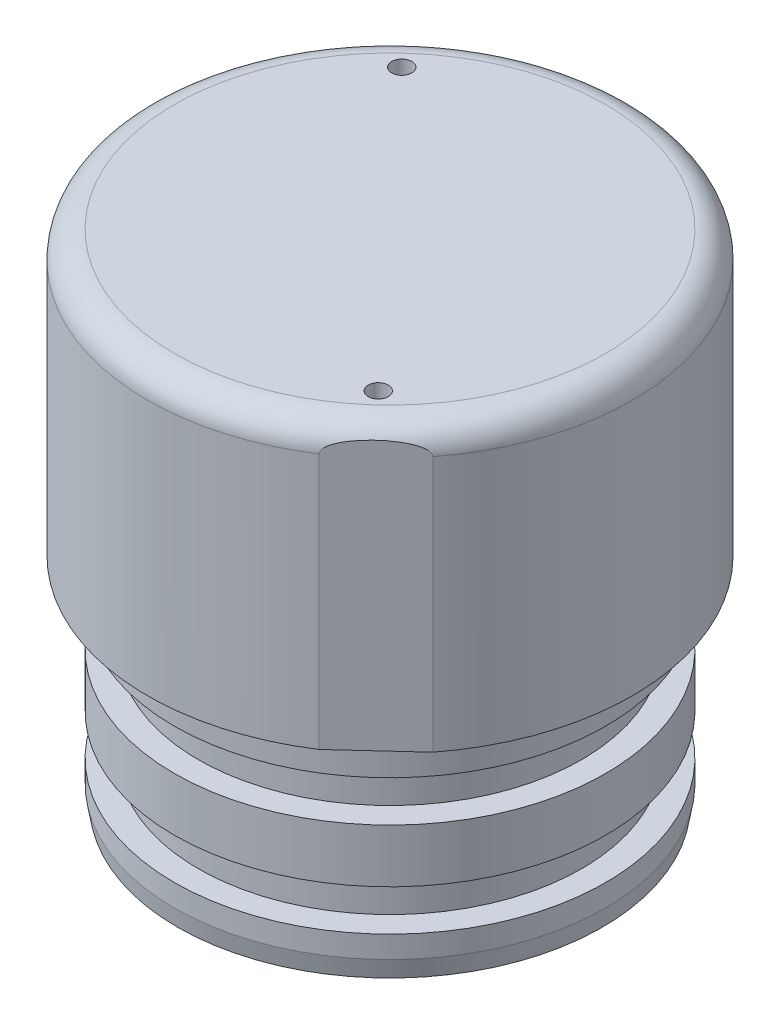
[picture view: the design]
ISO-10303-21;
HEADER;
FILE_DESCRIPTION(('STEP AP214'),'2;1');
FILE_NAME('part.step','',(''),(''),'','','');
FILE_SCHEMA(('AUTOMOTIVE_DESIGN { 1 0 10303 214 1 1 1 1 }'));
ENDSEC;
DATA;
#1=APPLICATION_CONTEXT('core data for automotive mechanical design processes');
#2=APPLICATION_PROTOCOL_DEFINITION('international standard','automotive_design',2000,#1);
#3=PRODUCT_CONTEXT('',#1,'mechanical');
#4=PRODUCT('Part','Part','',(#3));
#5=PRODUCT_RELATED_PRODUCT_CATEGORY('part','',(#4));
#6=PRODUCT_DEFINITION_FORMATION('','',#4);
#7=PRODUCT_DEFINITION_CONTEXT('part definition',#1,'design');
#8=PRODUCT_DEFINITION('design','',#6,#7);
#9=PRODUCT_DEFINITION_SHAPE('','',#8);
#10=(LENGTH_UNIT() NAMED_UNIT(*) SI_UNIT(.MILLI.,.METRE.));
#11=(NAMED_UNIT(*) PLANE_ANGLE_UNIT() SI_UNIT($,.RADIAN.));
#12=(NAMED_UNIT(*) SI_UNIT($,.STERADIAN.) SOLID_ANGLE_UNIT());
#13=UNCERTAINTY_MEASURE_WITH_UNIT(LENGTH_MEASURE(1.E-05),#10,'distance_accuracy_value','');
#14=(GEOMETRIC_REPRESENTATION_CONTEXT(3) GLOBAL_UNCERTAINTY_ASSIGNED_CONTEXT((#13)) GLOBAL_UNIT_ASSIGNED_CONTEXT((#10,
#11,#12)) REPRESENTATION_CONTEXT('',''));
#15=CARTESIAN_POINT('',(0.,0.,0.));
#16=DIRECTION('',(0.,0.,1.));
#17=DIRECTION('',(1.,0.,0.));
#18=AXIS2_PLACEMENT_3D('',#15,#16,#17);
#19=CARTESIAN_POINT('',(0.,0.,0.));
#20=DIRECTION('',(0.,1.,0.));
#21=DIRECTION('',(0.,0.,1.));
#22=AXIS2_PLACEMENT_3D('',#19,#20,#21);
#23=PLANE('',#22);
#24=CARTESIAN_POINT('',(0.,0.,0.));
#25=DIRECTION('',(0.,1.,0.));
#26=DIRECTION('',(0.,0.,1.));
#27=AXIS2_PLACEMENT_3D('',#24,#25,#26);
#28=CIRCLE('',#27,25.4);
#29=CARTESIAN_POINT('',(0.,0.,25.4));
#30=VERTEX_POINT('',#29);
#31=EDGE_CURVE('E132',#30,#30,#28,.T.);
#32=ORIENTED_EDGE('',*,*,#31,.T.);
#33=EDGE_LOOP('',(#32));
#34=FACE_BOUND('',#33,.T.);
#35=DIRECTION('',(-0.736097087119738,0.,0.676875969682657));
#36=VECTOR('',#35,1.);
#37=CARTESIAN_POINT('',(-19.0730956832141,0.,-20.7418357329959));
#38=LINE('',#37,#36);
#39=CARTESIAN_POINT('',(-15.5796269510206,0.,-23.9542449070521));
#40=VERTEX_POINT('',#39);
#41=CARTESIAN_POINT('',(-22.5665644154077,0.,-17.5294265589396));
#42=VERTEX_POINT('',#41);
#43=EDGE_CURVE('E106',#40,#42,#38,.T.);
#44=ORIENTED_EDGE('',*,*,#43,.F.);
#45=CARTESIAN_POINT('',(0.,0.,0.));
#46=DIRECTION('',(0.,1.,0.));
#47=DIRECTION('',(0.,0.,1.));
#48=AXIS2_PLACEMENT_3D('',#45,#46,#47);
#49=CIRCLE('',#48,28.575);
#50=CARTESIAN_POINT('',(22.5665644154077,0.,17.5294265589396));
#51=VERTEX_POINT('',#50);
#52=EDGE_CURVE('E127',#51,#40,#49,.T.);
#53=ORIENTED_EDGE('',*,*,#52,.F.);
#54=DIRECTION('',(0.736097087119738,0.,-0.676875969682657));
#55=VECTOR('',#54,1.);
#56=CARTESIAN_POINT('',(19.0730956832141,0.,20.7418357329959));
#57=LINE('',#56,#55);
#58=CARTESIAN_POINT('',(15.5796269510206,0.,23.9542449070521));
#59=VERTEX_POINT('',#58);
#60=EDGE_CURVE('E125',#59,#51,#57,.T.);
#61=ORIENTED_EDGE('',*,*,#60,.F.);
#62=EDGE_CURVE('E120',#42,#59,#49,.T.);
#63=ORIENTED_EDGE('',*,*,#62,.F.);
#64=EDGE_LOOP('',(#44,#53,#61,#63));
#65=FACE_BOUND('',#64,.T.);
#66=ADVANCED_FACE('F42',(#34,#65),#23,.F.);
#67=CARTESIAN_POINT('',(0.,30.1498,0.));
#68=DIRECTION('',(0.,1.,0.));
#69=DIRECTION('',(0.,0.,1.));
#70=AXIS2_PLACEMENT_3D('',#67,#68,#69);
#71=TOROIDAL_SURFACE('',#70,25.4,3.175);
#72=CARTESIAN_POINT('',(0.,33.3248,0.));
#73=DIRECTION('',(0.,1.,0.));
#74=DIRECTION('',(0.,0.,1.));
#75=AXIS2_PLACEMENT_3D('',#72,#73,#74);
#76=CIRCLE('',#75,25.4);
#77=CARTESIAN_POINT('',(0.,33.3248,25.4));
#78=VERTEX_POINT('',#77);
#79=EDGE_CURVE('E425',#78,#78,#76,.T.);
#80=ORIENTED_EDGE('',*,*,#79,.F.);
#81=EDGE_LOOP('',(#80));
#82=FACE_BOUND('',#81,.T.);
#83=CARTESIAN_POINT('',(0.,30.1498,0.));
#84=DIRECTION('',(0.,1.,0.));
#85=DIRECTION('',(0.,0.,1.));
#86=AXIS2_PLACEMENT_3D('',#83,#84,#85);
#87=CIRCLE('',#86,28.575);
#88=CARTESIAN_POINT('',(-15.5796269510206,30.1498000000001,-23.9542449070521));
#89=VERTEX_POINT('',#88);
#90=CARTESIAN_POINT('',(-0.531127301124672,30.1498,-28.5700635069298));
#91=VERTEX_POINT('',#90);
#92=EDGE_CURVE('E428',#89,#91,#87,.F.);
#93=ORIENTED_EDGE('',*,*,#92,.F.);
#94=CARTESIAN_POINT('',(-15.5817128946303,30.0951413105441,-23.952326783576));
#95=CARTESIAN_POINT('',(-15.5792110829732,30.1268458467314,-23.9546273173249));
#96=CARTESIAN_POINT('',(-15.5789577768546,30.1588034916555,-23.9548602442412));
#97=CARTESIAN_POINT('',(-15.5825959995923,30.2219737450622,-23.9515147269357));
#98=CARTESIAN_POINT('',(-15.5864466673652,30.2531905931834,-23.9479738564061));
#99=CARTESIAN_POINT('',(-15.5978925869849,30.3142250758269,-23.9374487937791));
#100=CARTESIAN_POINT('',(-15.6054798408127,30.3440455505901,-23.9304719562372));
#101=CARTESIAN_POINT('',(-15.62373561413,30.4019326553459,-23.913684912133));
#102=CARTESIAN_POINT('',(-15.634411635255,30.4299948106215,-23.9038678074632));
#103=CARTESIAN_POINT('',(-15.666442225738,30.5029551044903,-23.8744141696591));
#104=CARTESIAN_POINT('',(-15.6900628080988,30.5460059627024,-23.8526939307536));
#105=CARTESIAN_POINT('',(-15.741756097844,30.6268476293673,-23.8051595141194));
#106=CARTESIAN_POINT('',(-15.7698431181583,30.6646207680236,-23.779332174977));
#107=CARTESIAN_POINT('',(-15.8282739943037,30.7349283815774,-23.7256022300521));
#108=CARTESIAN_POINT('',(-15.858557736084,30.767556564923,-23.6977549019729));
#109=CARTESIAN_POINT('',(-15.9210431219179,30.8292576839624,-23.6402966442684));
#110=CARTESIAN_POINT('',(-15.9532466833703,30.8583269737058,-23.6106839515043));
#111=CARTESIAN_POINT('',(-16.051944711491,30.9411685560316,-23.5199264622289));
#112=CARTESIAN_POINT('',(-16.1204550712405,30.9904952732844,-23.4569279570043));
#113=CARTESIAN_POINT('',(-16.2454564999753,31.0709346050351,-23.3419832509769));
#114=CARTESIAN_POINT('',(-16.3014025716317,31.1036894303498,-23.2905382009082));
#115=CARTESIAN_POINT('',(-16.4145724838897,31.1648718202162,-23.1864731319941));
#116=CARTESIAN_POINT('',(-16.4717965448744,31.1932986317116,-23.1338529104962));
#117=CARTESIAN_POINT('',(-16.6450073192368,31.2733261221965,-22.9745774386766));
#118=CARTESIAN_POINT('',(-16.7623329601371,31.3195531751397,-22.8666909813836));
#119=CARTESIAN_POINT('',(-16.9996306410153,31.4016796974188,-22.6484845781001));
#120=CARTESIAN_POINT('',(-17.1196146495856,31.4375127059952,-22.5381536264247));
#121=CARTESIAN_POINT('',(-17.360652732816,31.5006063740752,-22.3165077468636));
#122=CARTESIAN_POINT('',(-17.4817055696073,31.5278758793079,-22.2051939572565));
#123=CARTESIAN_POINT('',(-17.7387193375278,31.578037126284,-21.9688576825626));
#124=CARTESIAN_POINT('',(-17.8747720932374,31.6000471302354,-21.8437507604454));
#125=CARTESIAN_POINT('',(-18.1474502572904,31.6363572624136,-21.5930103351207));
#126=CARTESIAN_POINT('',(-18.2840757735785,31.6506558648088,-21.467376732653));
#127=CARTESIAN_POINT('',(-18.5578202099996,31.6722442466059,-21.215655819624));
#128=CARTESIAN_POINT('',(-18.6949395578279,31.6795238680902,-21.0895681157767));
#129=CARTESIAN_POINT('',(-18.9692981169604,31.6873726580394,-20.8372824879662));
#130=CARTESIAN_POINT('',(-19.1065373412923,31.6879409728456,-20.7110845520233));
#131=CARTESIAN_POINT('',(-19.3801198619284,31.6824066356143,-20.4595125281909));
#132=CARTESIAN_POINT('',(-19.516463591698,31.6763440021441,-20.3341380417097));
#133=CARTESIAN_POINT('',(-19.7888760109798,31.6573402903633,-20.0836419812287));
#134=CARTESIAN_POINT('',(-19.9249447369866,31.644400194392,-19.9585203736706));
#135=CARTESIAN_POINT('',(-20.1963911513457,31.6110517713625,-19.7089126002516));
#136=CARTESIAN_POINT('',(-20.331769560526,31.5906544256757,-19.5844257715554));
#137=CARTESIAN_POINT('',(-20.6016643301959,31.5413398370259,-19.3362448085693));
#138=CARTESIAN_POINT('',(-20.7361809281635,31.5124250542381,-19.2125504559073));
#139=CARTESIAN_POINT('',(-20.9709106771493,31.4526842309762,-18.9967053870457));
#140=CARTESIAN_POINT('',(-21.0714264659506,31.4240759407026,-18.904276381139));
#141=CARTESIAN_POINT('',(-21.2713724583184,31.3597670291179,-18.7204166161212));
#142=CARTESIAN_POINT('',(-21.370801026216,31.3240569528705,-18.6289873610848));
#143=CARTESIAN_POINT('',(-21.5764714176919,31.2402462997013,-18.4398637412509));
#144=CARTESIAN_POINT('',(-21.6825416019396,31.1913311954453,-18.3423272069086));
#145=CARTESIAN_POINT('',(-21.8383726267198,31.1071934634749,-18.1990332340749));
#146=CARTESIAN_POINT('',(-21.8897171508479,31.0773911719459,-18.1518195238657));
#147=CARTESIAN_POINT('',(-21.9908870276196,31.0133899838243,-18.0587890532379));
#148=CARTESIAN_POINT('',(-22.0407133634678,30.9791940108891,-18.0129713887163));
#149=CARTESIAN_POINT('',(-22.1272225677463,30.9135727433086,-17.9334220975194));
#150=CARTESIAN_POINT('',(-22.1643514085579,30.8832400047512,-17.8992803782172));
#151=CARTESIAN_POINT('',(-22.2367405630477,30.818481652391,-17.8327151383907));
#152=CARTESIAN_POINT('',(-22.271997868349,30.784049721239,-17.8002943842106));
#153=CARTESIAN_POINT('',(-22.3399297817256,30.7098675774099,-17.7378277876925));
#154=CARTESIAN_POINT('',(-22.3725773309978,30.6700708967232,-17.7078068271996));
#155=CARTESIAN_POINT('',(-22.433160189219,30.5842733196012,-17.652098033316));
#156=CARTESIAN_POINT('',(-22.4611089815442,30.5382908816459,-17.6263978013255));
#157=CARTESIAN_POINT('',(-22.4990889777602,30.4602778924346,-17.5914734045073));
#158=CARTESIAN_POINT('',(-22.5116964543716,30.4305820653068,-17.5798802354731));
#159=CARTESIAN_POINT('',(-22.5335069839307,30.3690394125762,-17.5598244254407));
#160=CARTESIAN_POINT('',(-22.5427217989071,30.3372004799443,-17.5513509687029));
#161=CARTESIAN_POINT('',(-22.5570990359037,30.2708914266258,-17.5381304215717));
#162=CARTESIAN_POINT('',(-22.5621462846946,30.2363736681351,-17.5334892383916));
#163=CARTESIAN_POINT('',(-22.5672818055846,30.1661955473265,-17.5287668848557));
#164=CARTESIAN_POINT('',(-22.5672998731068,30.1305259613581,-17.5287502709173));
#165=CARTESIAN_POINT('',(-22.564478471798,30.0951413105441,-17.5313446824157));
#166=B_SPLINE_CURVE_WITH_KNOTS('',3,(#94,#95,#96,#97,#98,#99,#100,#101,#102,#103,#104,#105,#106,
#107,#108,#109,#110,#111,#112,#113,#114,#115,#116,#117,#118,#119,#120,#121,#122,#123,#124,#125,
#126,#127,#128,#129,#130,#131,#132,#133,#134,#135,#136,#137,#138,#139,#140,#141,#142,#143,#144,
#145,#146,#147,#148,#149,#150,#151,#152,#153,#154,#155,#156,#157,#158,#159,#160,#161,#162,#163,
#164,#165),.UNSPECIFIED.,.F.,.F.,(4,2,2,2,2,2,2,2,2,2,2,2,2,2,2,2,2,2,2,2,2,2,2,2,2,2,2,2,2,2,2,
2,2,2,2,4),(0.,0.0954121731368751,0.189883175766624,0.284152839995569,0.378653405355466,
0.538804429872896,0.699479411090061,0.856764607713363,1.01420961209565,1.32947221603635,
1.57764159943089,1.82585411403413,2.3231658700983,2.82359073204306,3.32349696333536,
3.8817176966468,4.4400488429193,4.99918680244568,5.55839588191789,6.11424859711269,
6.67002193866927,7.22498013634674,7.77977819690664,8.19817248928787,8.61712758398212,
9.07299893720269,9.3004461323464,9.52774275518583,9.70417258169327,9.88087791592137,
10.0592260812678,10.2370533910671,10.33959720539,10.4417820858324,10.5467044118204,
10.65309132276),.UNSPECIFIED.);
#167=CARTESIAN_POINT('',(-22.5665644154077,30.1498,-17.5294265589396));
#168=VERTEX_POINT('',#167);
#169=EDGE_CURVE('E114',#89,#168,#166,.T.);
#170=ORIENTED_EDGE('',*,*,#169,.T.);
#171=CARTESIAN_POINT('',(15.5796269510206,30.1498000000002,23.9542449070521));
#172=VERTEX_POINT('',#171);
#173=EDGE_CURVE('E123',#172,#168,#87,.F.);
#174=ORIENTED_EDGE('',*,*,#173,.F.);
#175=CARTESIAN_POINT('',(15.5817128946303,30.0951413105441,23.952326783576));
#176=CARTESIAN_POINT('',(15.5792110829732,30.1268458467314,23.9546273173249));
#177=CARTESIAN_POINT('',(15.5789577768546,30.1588034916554,23.9548602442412));
#178=CARTESIAN_POINT('',(15.5825959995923,30.2219737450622,23.9515147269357));
#179=CARTESIAN_POINT('',(15.5864466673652,30.2531905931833,23.9479738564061));
#180=CARTESIAN_POINT('',(15.5978925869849,30.3142250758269,23.9374487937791));
#181=CARTESIAN_POINT('',(15.6054798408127,30.3440455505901,23.9304719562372));
#182=CARTESIAN_POINT('',(15.62373561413,30.4019326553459,23.913684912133));
#183=CARTESIAN_POINT('',(15.634411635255,30.4299948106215,23.9038678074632));
#184=CARTESIAN_POINT('',(15.666442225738,30.5029551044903,23.8744141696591));
#185=CARTESIAN_POINT('',(15.6900628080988,30.5460059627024,23.8526939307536));
#186=CARTESIAN_POINT('',(15.741756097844,30.6268476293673,23.8051595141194));
#187=CARTESIAN_POINT('',(15.7698431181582,30.6646207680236,23.7793321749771));
#188=CARTESIAN_POINT('',(15.8282739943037,30.7349283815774,23.7256022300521));
#189=CARTESIAN_POINT('',(15.858557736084,30.767556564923,23.6977549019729));
#190=CARTESIAN_POINT('',(15.9210431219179,30.8292576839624,23.6402966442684));
#191=CARTESIAN_POINT('',(15.9532466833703,30.8583269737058,23.6106839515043));
#192=CARTESIAN_POINT('',(16.051944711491,30.9411685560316,23.5199264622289));
#193=CARTESIAN_POINT('',(16.1204550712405,30.9904952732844,23.4569279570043));
#194=CARTESIAN_POINT('',(16.2454564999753,31.0709346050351,23.3419832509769));
#195=CARTESIAN_POINT('',(16.3014025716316,31.1036894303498,23.2905382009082));
#196=CARTESIAN_POINT('',(16.4145724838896,31.1648718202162,23.1864731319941));
#197=CARTESIAN_POINT('',(16.4717965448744,31.1932986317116,23.1338529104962));
#198=CARTESIAN_POINT('',(16.6450073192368,31.2733261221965,22.9745774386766));
#199=CARTESIAN_POINT('',(16.7623329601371,31.3195531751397,22.8666909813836));
#200=CARTESIAN_POINT('',(16.9996306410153,31.4016796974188,22.6484845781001));
#201=CARTESIAN_POINT('',(17.1196146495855,31.4375127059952,22.5381536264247));
#202=CARTESIAN_POINT('',(17.3606527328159,31.5006063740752,22.3165077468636));
#203=CARTESIAN_POINT('',(17.4817055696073,31.5278758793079,22.2051939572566));
#204=CARTESIAN_POINT('',(17.7387193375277,31.578037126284,21.9688576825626));
#205=CARTESIAN_POINT('',(17.8747720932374,31.6000471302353,21.8437507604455));
#206=CARTESIAN_POINT('',(18.1474502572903,31.6363572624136,21.5930103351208));
#207=CARTESIAN_POINT('',(18.2840757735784,31.6506558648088,21.467376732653));
#208=CARTESIAN_POINT('',(18.5578202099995,31.6722442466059,21.2156558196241));
#209=CARTESIAN_POINT('',(18.6949395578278,31.6795238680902,21.0895681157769));
#210=CARTESIAN_POINT('',(18.9692981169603,31.6873726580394,20.8372824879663));
#211=CARTESIAN_POINT('',(19.1065373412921,31.6879409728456,20.7110845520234));
#212=CARTESIAN_POINT('',(19.3801198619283,31.6824066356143,20.459512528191));
#213=CARTESIAN_POINT('',(19.5164635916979,31.6763440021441,20.3341380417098));
#214=CARTESIAN_POINT('',(19.7888760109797,31.6573402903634,20.0836419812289));
#215=CARTESIAN_POINT('',(19.9249447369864,31.644400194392,19.9585203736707));
#216=CARTESIAN_POINT('',(20.1963911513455,31.6110517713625,19.7089126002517));
#217=CARTESIAN_POINT('',(20.3317695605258,31.5906544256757,19.5844257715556));
#218=CARTESIAN_POINT('',(20.6016643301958,31.541339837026,19.3362448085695));
#219=CARTESIAN_POINT('',(20.7361809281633,31.5124250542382,19.2125504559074));
#220=CARTESIAN_POINT('',(20.9709106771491,31.4526842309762,18.9967053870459));
#221=CARTESIAN_POINT('',(21.0714264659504,31.4240759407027,18.9042763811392));
#222=CARTESIAN_POINT('',(21.2713724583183,31.3597670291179,18.7204166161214));
#223=CARTESIAN_POINT('',(21.3708010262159,31.3240569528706,18.6289873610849));
#224=CARTESIAN_POINT('',(21.5764714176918,31.2402462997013,18.439863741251));
#225=CARTESIAN_POINT('',(21.6825416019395,31.1913311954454,18.3423272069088));
#226=CARTESIAN_POINT('',(21.8383726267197,31.107193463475,18.199033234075));
#227=CARTESIAN_POINT('',(21.8897171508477,31.0773911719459,18.1518195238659));
#228=CARTESIAN_POINT('',(21.9908870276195,31.0133899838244,18.058789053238));
#229=CARTESIAN_POINT('',(22.0407133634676,30.9791940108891,18.0129713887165));
#230=CARTESIAN_POINT('',(22.1272225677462,30.9135727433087,17.9334220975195));
#231=CARTESIAN_POINT('',(22.1643514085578,30.8832400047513,17.8992803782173));
#232=CARTESIAN_POINT('',(22.2367405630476,30.8184816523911,17.8327151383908));
#233=CARTESIAN_POINT('',(22.2719978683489,30.7840497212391,17.8002943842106));
#234=CARTESIAN_POINT('',(22.3399297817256,30.70986757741,17.7378277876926));
#235=CARTESIAN_POINT('',(22.3725773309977,30.6700708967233,17.7078068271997));
#236=CARTESIAN_POINT('',(22.433160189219,30.5842733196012,17.6520980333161));
#237=CARTESIAN_POINT('',(22.4611089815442,30.5382908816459,17.6263978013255));
#238=CARTESIAN_POINT('',(22.4990889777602,30.4602778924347,17.5914734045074));
#239=CARTESIAN_POINT('',(22.5116964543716,30.4305820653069,17.5798802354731));
#240=CARTESIAN_POINT('',(22.5335069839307,30.3690394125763,17.5598244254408));
#241=CARTESIAN_POINT('',(22.542721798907,30.3372004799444,17.5513509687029));
#242=CARTESIAN_POINT('',(22.5570990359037,30.2708914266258,17.5381304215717));
#243=CARTESIAN_POINT('',(22.5621462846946,30.2363736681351,17.5334892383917));
#244=CARTESIAN_POINT('',(22.5672818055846,30.1661955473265,17.5287668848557));
#245=CARTESIAN_POINT('',(22.5672998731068,30.1305259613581,17.5287502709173));
#246=CARTESIAN_POINT('',(22.564478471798,30.0951413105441,17.5313446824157));
#247=B_SPLINE_CURVE_WITH_KNOTS('',3,(#175,#176,#177,#178,#179,#180,#181,#182,#183,#184,#185,
#186,#187,#188,#189,#190,#191,#192,#193,#194,#195,#196,#197,#198,#199,#200,#201,#202,#203,#204,
#205,#206,#207,#208,#209,#210,#211,#212,#213,#214,#215,#216,#217,#218,#219,#220,#221,#222,#223,
#224,#225,#226,#227,#228,#229,#230,#231,#232,#233,#234,#235,#236,#237,#238,#239,#240,#241,#242,
#243,#244,#245,#246),.UNSPECIFIED.,.F.,.F.,(4,2,2,2,2,2,2,2,2,2,2,2,2,2,2,2,2,2,2,2,2,2,2,2,2,2,
2,2,2,2,2,2,2,2,2,4),(0.,0.0954121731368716,0.189883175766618,0.28415283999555,
0.378653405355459,0.538804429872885,0.699479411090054,0.856764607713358,1.01420961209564,
1.32947221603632,1.57764159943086,1.82585411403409,2.32316587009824,2.82359073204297,
3.32349696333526,3.88171769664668,4.44004884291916,4.99918680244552,5.5583958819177,
6.11424859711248,6.67002193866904,7.22498013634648,7.77977819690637,8.19817248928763,
8.61712758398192,9.07299893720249,9.3004461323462,9.52774275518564,9.7041725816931,
9.88087791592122,10.0592260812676,10.237053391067,10.3395972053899,10.4417820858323,
10.5467044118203,10.65309132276),.UNSPECIFIED.);
#248=CARTESIAN_POINT('',(22.5665644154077,30.1498,17.5294265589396));
#249=VERTEX_POINT('',#248);
#250=EDGE_CURVE('E47',#172,#249,#247,.T.);
#251=ORIENTED_EDGE('',*,*,#250,.T.);
#252=CARTESIAN_POINT('',(0.531127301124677,30.1498,-28.5700635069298));
#253=VERTEX_POINT('',#252);
#254=EDGE_CURVE('E433',#253,#249,#87,.F.);
#255=ORIENTED_EDGE('',*,*,#254,.F.);
#256=CARTESIAN_POINT('',(-0.531127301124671,30.1498,-28.5700635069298));
#257=CARTESIAN_POINT('',(-0.354084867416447,30.1582666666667,-28.5733375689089));
#258=CARTESIAN_POINT('',(-0.177042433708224,30.1625,-28.5749745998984));
#259=CARTESIAN_POINT('',(0.177042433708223,30.1625,-28.5749745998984));
#260=CARTESIAN_POINT('',(0.354084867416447,30.1582666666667,-28.5733375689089));
#261=CARTESIAN_POINT('',(0.531127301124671,30.1498,-28.5700635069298));
#262=B_SPLINE_CURVE_WITH_KNOTS('',3,(#256,#257,#258,#259,#260,#261),.UNSPECIFIED.,.F.,.F.,(4,2,
4),(0.,0.531301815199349,1.0626036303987),.UNSPECIFIED.);
#263=EDGE_CURVE('E436',#91,#253,#262,.T.);
#264=ORIENTED_EDGE('',*,*,#263,.F.);
#265=EDGE_LOOP('',(#93,#170,#174,#251,#255,#264));
#266=FACE_BOUND('',#265,.T.);
#267=ADVANCED_FACE('F44',(#82,#266),#71,.T.);
#268=CARTESIAN_POINT('',(0.,33.3248,0.));
#269=DIRECTION('',(0.,-1.,0.));
#270=DIRECTION('',(0.,0.,-1.));
#271=AXIS2_PLACEMENT_3D('',#268,#269,#270);
#272=CYLINDRICAL_SURFACE('',#271,28.575);
#273=DIRECTION('',(0.,-1.,0.));
#274=VECTOR('',#273,1.);
#275=CARTESIAN_POINT('',(-15.5796269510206,199.899972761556,-23.9542449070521));
#276=LINE('',#275,#274);
#277=EDGE_CURVE('E58',#89,#40,#276,.T.);
#278=ORIENTED_EDGE('',*,*,#277,.F.);
#279=ORIENTED_EDGE('',*,*,#92,.T.);
#280=CARTESIAN_POINT('',(0.,30.1625,-28.575));
#281=CARTESIAN_POINT('',(-0.300085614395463,30.1625019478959,-28.5750014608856));
#282=CARTESIAN_POINT('',(-0.600145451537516,30.150335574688,-28.5702629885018));
#283=CARTESIAN_POINT('',(-1.1979826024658,30.101805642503,-28.551442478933));
#284=CARTESIAN_POINT('',(-1.49576016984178,30.065444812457,-28.5373614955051));
#285=CARTESIAN_POINT('',(-2.0867849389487,29.9689116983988,-28.5002390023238));
#286=CARTESIAN_POINT('',(-2.38003312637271,29.9087446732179,-28.477199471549));
#287=CARTESIAN_POINT('',(-2.95999972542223,29.7651903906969,-28.4227702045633));
#288=CARTESIAN_POINT('',(-3.24671791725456,29.6818023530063,-28.3913801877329));
#289=CARTESIAN_POINT('',(-3.81104373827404,29.4927943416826,-28.3211448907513));
#290=CARTESIAN_POINT('',(-4.08867058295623,29.3872252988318,-28.2823167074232));
#291=CARTESIAN_POINT('',(-4.63385527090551,29.1545986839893,-28.1981227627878));
#292=CARTESIAN_POINT('',(-4.90140933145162,29.0275331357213,-28.1527545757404));
#293=CARTESIAN_POINT('',(-5.42477403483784,28.7529282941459,-28.0566079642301));
#294=CARTESIAN_POINT('',(-5.68058451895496,28.6053887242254,-28.0058294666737));
#295=CARTESIAN_POINT('',(-6.17906364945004,28.2908707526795,-27.9000847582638));
#296=CARTESIAN_POINT('',(-6.42173134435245,28.1238909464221,-27.8451182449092));
#297=CARTESIAN_POINT('',(-6.90221905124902,27.7643949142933,-27.7300105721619));
#298=CARTESIAN_POINT('',(-7.13944006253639,27.5711160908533,-27.6697498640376));
#299=CARTESIAN_POINT('',(-7.59692811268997,27.1658931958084,-27.5476563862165));
#300=CARTESIAN_POINT('',(-7.81719479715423,26.9539487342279,-27.4858235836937));
#301=CARTESIAN_POINT('',(-8.2396079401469,26.512563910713,-27.3621625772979));
#302=CARTESIAN_POINT('',(-8.44174817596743,26.2831175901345,-27.3003343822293));
#303=CARTESIAN_POINT('',(-8.82662744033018,25.8080878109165,-27.1783376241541));
#304=CARTESIAN_POINT('',(-9.00936691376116,25.5625047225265,-27.1181690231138));
#305=CARTESIAN_POINT('',(-9.36153094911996,25.045928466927,-26.9986737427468));
#306=CARTESIAN_POINT('',(-9.53007548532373,24.7743015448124,-26.9394882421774));
#307=CARTESIAN_POINT('',(-9.84348993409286,24.2167768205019,-26.8265555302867));
#308=CARTESIAN_POINT('',(-9.9883693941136,23.930884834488,-26.7728061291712));
#309=CARTESIAN_POINT('',(-10.2532705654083,23.3466222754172,-26.6724790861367));
#310=CARTESIAN_POINT('',(-10.3732952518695,23.0482532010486,-26.6259005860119));
#311=CARTESIAN_POINT('',(-10.587329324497,22.441120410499,-26.5415209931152));
#312=CARTESIAN_POINT('',(-10.6813403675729,22.1323573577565,-26.5037193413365));
#313=CARTESIAN_POINT('',(-10.8388318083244,21.5203906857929,-26.4396910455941));
#314=CARTESIAN_POINT('',(-10.9034605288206,21.2175277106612,-26.4130331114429));
#315=CARTESIAN_POINT('',(-11.0072763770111,20.6067484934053,-26.3699386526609));
#316=CARTESIAN_POINT('',(-11.0464642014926,20.2988323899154,-26.3535018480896));
#317=CARTESIAN_POINT('',(-11.0989327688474,19.6805340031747,-26.3314475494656));
#318=CARTESIAN_POINT('',(-11.1122236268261,19.370152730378,-26.3258258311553));
#319=CARTESIAN_POINT('',(-11.1127677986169,18.7493700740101,-26.3255963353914));
#320=CARTESIAN_POINT('',(-11.1000222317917,18.4389686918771,-26.3309880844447));
#321=CARTESIAN_POINT('',(-11.050330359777,17.8408906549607,-26.3518780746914));
#322=CARTESIAN_POINT('',(-11.0150171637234,17.5530525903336,-26.3666940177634));
#323=CARTESIAN_POINT('',(-10.9221439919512,16.9816163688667,-26.4053010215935));
#324=CARTESIAN_POINT('',(-10.8645851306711,16.6980180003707,-26.4290916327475));
#325=CARTESIAN_POINT('',(-10.7277667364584,16.1369116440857,-26.4849220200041));
#326=CARTESIAN_POINT('',(-10.6485047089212,15.8594043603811,-26.5169627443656));
#327=CARTESIAN_POINT('',(-10.468986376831,15.3122339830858,-26.5883483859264));
#328=CARTESIAN_POINT('',(-10.3687293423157,15.0425711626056,-26.6276935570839));
#329=CARTESIAN_POINT('',(-10.1458746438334,14.5074768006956,-26.7134118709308));
#330=CARTESIAN_POINT('',(-10.02287880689,14.2422308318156,-26.7599072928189));
#331=CARTESIAN_POINT('',(-9.75678710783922,13.7229064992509,-26.858068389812));
#332=CARTESIAN_POINT('',(-9.61368389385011,13.4688322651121,-26.9097359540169));
#333=CARTESIAN_POINT('',(-9.30835793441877,12.9732537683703,-27.0168700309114));
#334=CARTESIAN_POINT('',(-9.14613305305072,12.7317509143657,-27.0723369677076));
#335=CARTESIAN_POINT('',(-8.80355729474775,12.2625540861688,-27.1856681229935));
#336=CARTESIAN_POINT('',(-8.62320553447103,12.0348607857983,-27.2435324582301));
#337=CARTESIAN_POINT('',(-8.23157561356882,11.5783374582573,-27.3645169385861));
#338=CARTESIAN_POINT('',(-8.01900089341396,11.3506380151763,-27.4277123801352));
#339=CARTESIAN_POINT('',(-7.57550101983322,10.9138911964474,-27.5535026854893));
#340=CARTESIAN_POINT('',(-7.34458322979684,10.7048364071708,-27.6160977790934));
#341=CARTESIAN_POINT('',(-6.8655078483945,10.3064557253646,-27.7390809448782));
#342=CARTESIAN_POINT('',(-6.61733983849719,10.117141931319,-27.799467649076));
#343=CARTESIAN_POINT('',(-6.10543943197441,9.75975425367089,-27.916359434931));
#344=CARTESIAN_POINT('',(-5.8417134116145,9.59167175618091,-27.9728660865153));
#345=CARTESIAN_POINT('',(-5.29530127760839,9.27508721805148,-28.0814774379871));
#346=CARTESIAN_POINT('',(-5.01235893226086,9.12699316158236,-28.1334843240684));
#347=CARTESIAN_POINT('',(-4.4337605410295,8.855316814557,-28.2304520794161));
#348=CARTESIAN_POINT('',(-4.13810423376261,8.73173502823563,-28.2754128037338));
#349=CARTESIAN_POINT('',(-3.53630462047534,8.51031507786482,-28.3569626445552));
#350=CARTESIAN_POINT('',(-3.23016542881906,8.41246694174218,-28.3935550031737));
#351=CARTESIAN_POINT('',(-2.60964328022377,8.24348355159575,-28.4572948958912));
#352=CARTESIAN_POINT('',(-2.29526086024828,8.17234656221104,-28.4844430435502));
#353=CARTESIAN_POINT('',(-1.67875195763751,8.06082518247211,-28.5272228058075));
#354=CARTESIAN_POINT('',(-1.37693727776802,8.01892969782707,-28.5434186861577));
#355=CARTESIAN_POINT('',(-0.770529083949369,7.96006188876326,-28.5662205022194));
#356=CARTESIAN_POINT('',(-0.465935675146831,7.94308862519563,-28.5728267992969));
#357=CARTESIAN_POINT('',(0.143604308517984,7.934248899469,-28.5762642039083));
#358=CARTESIAN_POINT('',(0.448550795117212,7.9423771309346,-28.5730973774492));
#359=CARTESIAN_POINT('',(1.05648660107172,7.98364065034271,-28.5570817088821));
#360=CARTESIAN_POINT('',(1.35947595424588,8.01677550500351,-28.5442330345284));
#361=CARTESIAN_POINT('',(1.94851837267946,8.10578239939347,-28.5099502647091));
#362=CARTESIAN_POINT('',(2.23474793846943,8.16063997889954,-28.4888998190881));
#363=CARTESIAN_POINT('',(2.80133973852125,8.29245617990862,-28.4387764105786));
#364=CARTESIAN_POINT('',(3.08170217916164,8.36941402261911,-28.4097037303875));
#365=CARTESIAN_POINT('',(3.63473571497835,8.54473959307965,-28.3442561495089));
#366=CARTESIAN_POINT('',(3.90740752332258,8.64310532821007,-28.307881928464));
#367=CARTESIAN_POINT('',(4.44353806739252,8.86047914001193,-28.2286921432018));
#368=CARTESIAN_POINT('',(4.70699325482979,8.97949506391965,-28.1858741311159));
#369=CARTESIAN_POINT('',(5.23077023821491,9.2410795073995,-28.0934597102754));
#370=CARTESIAN_POINT('',(5.49076579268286,9.38424324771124,-28.0436995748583));
#371=CARTESIAN_POINT('',(5.99790649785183,9.69048319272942,-27.939627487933));
#372=CARTESIAN_POINT('',(6.24504719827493,9.85356622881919,-27.885313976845));
#373=CARTESIAN_POINT('',(6.72509949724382,10.1985552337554,-27.7734480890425));
#374=CARTESIAN_POINT('',(6.95800882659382,10.3804641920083,-27.7158951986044));
#375=CARTESIAN_POINT('',(7.40834894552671,10.7619891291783,-27.5989334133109));
#376=CARTESIAN_POINT('',(7.62577908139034,10.9616058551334,-27.5395244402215));
#377=CARTESIAN_POINT('',(8.05714025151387,11.3904734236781,-27.4165373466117));
#378=CARTESIAN_POINT('',(8.26999777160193,11.6207974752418,-27.3529313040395));
#379=CARTESIAN_POINT('',(8.67558206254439,12.0987314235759,-27.2270084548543));
#380=CARTESIAN_POINT('',(8.86831516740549,12.3463358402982,-27.1646912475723));
#381=CARTESIAN_POINT('',(9.23257183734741,12.8575982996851,-27.0430608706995));
#382=CARTESIAN_POINT('',(9.40408394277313,13.121264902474,-26.9837493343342));
#383=CARTESIAN_POINT('',(9.72446958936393,13.6628584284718,-26.8699500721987));
#384=CARTESIAN_POINT('',(9.87335265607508,13.9407792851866,-26.8154603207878));
#385=CARTESIAN_POINT('',(10.1483662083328,14.5113502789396,-26.7126003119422));
#386=CARTESIAN_POINT('',(10.2743217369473,14.8040935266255,-26.6642778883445));
#387=CARTESIAN_POINT('',(10.5009533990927,15.4004287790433,-26.5758427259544));
#388=CARTESIAN_POINT('',(10.6016292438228,15.70402090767,-26.5357300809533));
#389=CARTESIAN_POINT('',(10.7765992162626,16.3196337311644,-26.4651552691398));
#390=CARTESIAN_POINT('',(10.8509084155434,16.6316495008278,-26.4346875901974));
#391=CARTESIAN_POINT('',(10.9723659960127,17.2617700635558,-26.384505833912));
#392=CARTESIAN_POINT('',(11.0195164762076,17.5798743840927,-26.3647909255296));
#393=CARTESIAN_POINT('',(11.0838003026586,18.1975201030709,-26.3378266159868));
#394=CARTESIAN_POINT('',(11.1027705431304,18.4968383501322,-26.3298150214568));
#395=CARTESIAN_POINT('',(11.1164448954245,19.0961209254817,-26.3240449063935));
#396=CARTESIAN_POINT('',(11.1111501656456,19.3960852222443,-26.3262858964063));
#397=CARTESIAN_POINT('',(11.076357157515,19.9943192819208,-26.3409431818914));
#398=CARTESIAN_POINT('',(11.0468613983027,20.2925892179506,-26.3533584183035));
#399=CARTESIAN_POINT('',(10.9639937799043,20.8852150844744,-26.3879418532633));
#400=CARTESIAN_POINT('',(10.9106219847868,21.1795710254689,-26.4101100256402));
#401=CARTESIAN_POINT('',(10.7828801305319,21.7518576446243,-26.4625149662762));
#402=CARTESIAN_POINT('',(10.7093252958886,22.0299999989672,-26.4924363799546));
#403=CARTESIAN_POINT('',(10.5411660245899,22.5790124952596,-26.5597937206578));
#404=CARTESIAN_POINT('',(10.4465542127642,22.849880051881,-26.5972322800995));
#405=CARTESIAN_POINT('',(10.2370928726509,23.3826083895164,-26.6785524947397));
#406=CARTESIAN_POINT('',(10.1222467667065,23.6444706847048,-26.7224330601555));
#407=CARTESIAN_POINT('',(9.87311158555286,24.1579140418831,-26.8154800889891));
#408=CARTESIAN_POINT('',(9.73881495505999,24.4094910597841,-26.8646486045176));
#409=CARTESIAN_POINT('',(9.44383576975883,24.9144466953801,-26.9698057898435));
#410=CARTESIAN_POINT('',(9.28211111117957,25.1671697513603,-27.0260204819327));
#411=CARTESIAN_POINT('',(8.93905623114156,25.6583827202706,-27.1414195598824));
#412=CARTESIAN_POINT('',(8.75771716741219,25.8968661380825,-27.2006052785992));
#413=CARTESIAN_POINT('',(8.37656770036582,26.3582356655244,-27.3203886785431));
#414=CARTESIAN_POINT('',(8.17675589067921,26.581120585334,-27.380986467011));
#415=CARTESIAN_POINT('',(7.75979264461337,27.0100719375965,-27.5020611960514));
#416=CARTESIAN_POINT('',(7.54264085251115,27.2161380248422,-27.5625381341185));
#417=CARTESIAN_POINT('',(7.07857943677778,27.6221673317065,-27.6854718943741));
#418=CARTESIAN_POINT('',(6.8306651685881,27.8210147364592,-27.7478284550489));
#419=CARTESIAN_POINT('',(6.31824141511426,28.1970454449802,-27.8689743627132));
#420=CARTESIAN_POINT('',(6.0537380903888,28.3742367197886,-27.9277650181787));
#421=CARTESIAN_POINT('',(5.50949886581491,28.7058100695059,-28.0402084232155));
#422=CARTESIAN_POINT('',(5.22975299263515,28.8601769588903,-28.0938577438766));
#423=CARTESIAN_POINT('',(4.65714609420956,29.144592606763,-28.1944334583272));
#424=CARTESIAN_POINT('',(4.3642905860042,29.2746514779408,-28.2413626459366));
#425=CARTESIAN_POINT('',(3.74477808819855,29.5182027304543,-28.330414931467));
#426=CARTESIAN_POINT('',(3.41724042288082,29.6296961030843,-28.3719054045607));
#427=CARTESIAN_POINT('',(2.75205803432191,29.821893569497,-28.4441333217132));
#428=CARTESIAN_POINT('',(2.41441247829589,29.9025951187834,-28.4748698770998));
#429=CARTESIAN_POINT('',(1.73237374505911,30.0321201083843,-28.5244868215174));
#430=CARTESIAN_POINT('',(1.38798409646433,30.0809597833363,-28.5433732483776));
#431=CARTESIAN_POINT('',(0.69571771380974,30.1461460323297,-28.5686280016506));
#432=CARTESIAN_POINT('',(0.347841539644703,30.162497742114,-28.5749983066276));
#433=CARTESIAN_POINT('',(0.,30.1625,-28.575));
#434=B_SPLINE_CURVE_WITH_KNOTS('',3,(#280,#281,#282,#283,#284,#285,#286,#287,#288,#289,#290,
#291,#292,#293,#294,#295,#296,#297,#298,#299,#300,#301,#302,#303,#304,#305,#306,#307,#308,#309,
#310,#311,#312,#313,#314,#315,#316,#317,#318,#319,#320,#321,#322,#323,#324,#325,#326,#327,#328,
#329,#330,#331,#332,#333,#334,#335,#336,#337,#338,#339,#340,#341,#342,#343,#344,#345,#346,#347,
#348,#349,#350,#351,#352,#353,#354,#355,#356,#357,#358,#359,#360,#361,#362,#363,#364,#365,#366,
#367,#368,#369,#370,#371,#372,#373,#374,#375,#376,#377,#378,#379,#380,#381,#382,#383,#384,#385,
#386,#387,#388,#389,#390,#391,#392,#393,#394,#395,#396,#397,#398,#399,#400,#401,#402,#403,#404,
#405,#406,#407,#408,#409,#410,#411,#412,#413,#414,#415,#416,#417,#418,#419,#420,#421,#422,#423,
#424,#425,#426,#427,#428,#429,#430,#431,#432,#433),.UNSPECIFIED.,.T.,.F.,(4,2,2,2,2,2,2,2,2,2,2,
2,2,2,2,2,2,2,2,2,2,2,2,2,2,2,2,2,2,2,2,2,2,2,2,2,2,2,2,2,2,2,2,2,2,2,2,2,2,2,2,2,2,2,2,2,2,2,2,
2,2,2,2,2,2,2,2,2,2,2,2,2,2,2,2,2,4),(0.,0.899929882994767,1.79975827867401,2.69938801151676,
3.59904798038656,4.496664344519,5.39461450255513,6.29257679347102,7.19060400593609,
8.12517082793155,9.05975718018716,9.99466315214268,10.9295476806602,11.9036466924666,
12.8773517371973,13.8509401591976,14.8244665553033,15.7557258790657,16.6869596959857,
17.6178297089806,18.5486597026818,19.4187621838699,20.2888210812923,21.1589800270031,
22.0291692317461,22.9163579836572,23.8038719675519,24.6914851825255,25.5791416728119,
26.531602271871,27.483682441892,28.4363427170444,29.3886152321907,30.3580686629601,
31.3275420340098,32.296639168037,33.2656733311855,34.1799289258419,35.0941500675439,
36.0081779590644,36.9221900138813,37.7977760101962,38.6733311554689,39.5488048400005,
40.4246119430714,41.3264672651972,42.2286327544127,43.1309417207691,44.0332887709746,
44.9921936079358,45.9507957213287,46.9099132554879,47.8686259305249,48.8343729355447,
49.8001309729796,50.7653360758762,51.7304665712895,52.6294052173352,53.528300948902,
54.4271031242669,55.325902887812,56.1927037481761,57.0598086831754,57.9267671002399,
58.7940631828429,59.7088464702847,60.62404387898,61.5393110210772,62.4545969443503,
63.4250313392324,64.3951074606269,65.3658261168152,66.336140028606,67.3798966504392,
68.4237395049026,69.4670500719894,70.5101956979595),.UNSPECIFIED.);
#435=EDGE_CURVE('E168',#91,#253,#434,.T.);
#436=ORIENTED_EDGE('',*,*,#435,.T.);
#437=ORIENTED_EDGE('',*,*,#254,.T.);
#438=DIRECTION('',(0.,-1.,0.));
#439=VECTOR('',#438,1.);
#440=CARTESIAN_POINT('',(22.5665644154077,211.806222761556,17.5294265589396));
#441=LINE('',#440,#439);
#442=EDGE_CURVE('E72',#249,#51,#441,.T.);
#443=ORIENTED_EDGE('',*,*,#442,.T.);
#444=ORIENTED_EDGE('',*,*,#52,.T.);
#445=EDGE_LOOP('',(#278,#279,#436,#437,#443,#444));
#446=FACE_BOUND('',#445,.T.);
#447=ADVANCED_FACE('F227',(#446),#272,.T.);
#448=CARTESIAN_POINT('',(0.,-25.4,0.));
#449=DIRECTION('',(0.,1.,0.));
#450=DIRECTION('',(0.,0.,1.));
#451=AXIS2_PLACEMENT_3D('',#448,#449,#450);
#452=CYLINDRICAL_SURFACE('',#451,25.4);
#453=CARTESIAN_POINT('',(0.,-9.525,0.));
#454=DIRECTION('',(0.,-1.,0.));
#455=DIRECTION('',(0.,0.,-1.));
#456=AXIS2_PLACEMENT_3D('',#453,#454,#455);
#457=CIRCLE('',#456,25.4);
#458=CARTESIAN_POINT('',(0.,-9.525,-25.4));
#459=VERTEX_POINT('',#458);
#460=EDGE_CURVE('E151',#459,#459,#457,.F.);
#461=ORIENTED_EDGE('',*,*,#460,.F.);
#462=EDGE_LOOP('',(#461));
#463=FACE_BOUND('',#462,.T.);
#464=CARTESIAN_POINT('',(0.,-15.8242,0.));
#465=DIRECTION('',(0.,-1.,0.));
#466=DIRECTION('',(0.,0.,-1.));
#467=AXIS2_PLACEMENT_3D('',#464,#465,#466);
#468=CIRCLE('',#467,25.4);
#469=CARTESIAN_POINT('',(0.,-15.8242,-25.4));
#470=VERTEX_POINT('',#469);
#471=EDGE_CURVE('E146',#470,#470,#468,.F.);
#472=ORIENTED_EDGE('',*,*,#471,.T.);
#473=EDGE_LOOP('',(#472));
#474=FACE_BOUND('',#473,.T.);
#475=ADVANCED_FACE('F235',(#463,#474),#452,.T.);
#476=CARTESIAN_POINT('',(0.,-15.8242,0.));
#477=DIRECTION('',(0.,-1.,0.));
#478=DIRECTION('',(0.,0.,-1.));
#479=AXIS2_PLACEMENT_3D('',#476,#477,#478);
#480=PLANE('',#479);
#481=ORIENTED_EDGE('',*,*,#471,.F.);
#482=EDGE_LOOP('',(#481));
#483=FACE_BOUND('',#482,.T.);
#484=CARTESIAN_POINT('',(0.,-15.8242,0.));
#485=DIRECTION('',(0.,-1.,0.));
#486=DIRECTION('',(0.,0.,-1.));
#487=AXIS2_PLACEMENT_3D('',#484,#485,#486);
#488=CIRCLE('',#487,22.5806);
#489=CARTESIAN_POINT('',(0.,-15.8242,-22.5806));
#490=VERTEX_POINT('',#489);
#491=EDGE_CURVE('E147',#490,#490,#488,.T.);
#492=ORIENTED_EDGE('',*,*,#491,.F.);
#493=EDGE_LOOP('',(#492));
#494=FACE_BOUND('',#493,.T.);
#495=ADVANCED_FACE('F272',(#483,#494),#480,.T.);
#496=CARTESIAN_POINT('',(0.,-20.6502,0.));
#497=DIRECTION('',(0.,-1.,0.));
#498=DIRECTION('',(0.,0.,-1.));
#499=AXIS2_PLACEMENT_3D('',#496,#497,#498);
#500=PLANE('',#499);
#501=CARTESIAN_POINT('',(0.,-20.6502,0.));
#502=DIRECTION('',(0.,-1.,0.));
#503=DIRECTION('',(0.,0.,-1.));
#504=AXIS2_PLACEMENT_3D('',#501,#502,#503);
#505=CIRCLE('',#504,25.4);
#506=CARTESIAN_POINT('',(0.,-20.6502,-25.4));
#507=VERTEX_POINT('',#506);
#508=EDGE_CURVE('E142',#507,#507,#505,.F.);
#509=ORIENTED_EDGE('',*,*,#508,.T.);
#510=EDGE_LOOP('',(#509));
#511=FACE_BOUND('',#510,.T.);
#512=CARTESIAN_POINT('',(0.,-20.6502,0.));
#513=DIRECTION('',(0.,-1.,0.));
#514=DIRECTION('',(0.,0.,-1.));
#515=AXIS2_PLACEMENT_3D('',#512,#513,#514);
#516=CIRCLE('',#515,22.5806);
#517=CARTESIAN_POINT('',(0.,-20.6502,-22.5806));
#518=VERTEX_POINT('',#517);
#519=EDGE_CURVE('E160',#518,#518,#516,.T.);
#520=ORIENTED_EDGE('',*,*,#519,.T.);
#521=EDGE_LOOP('',(#520));
#522=FACE_BOUND('',#521,.T.);
#523=ADVANCED_FACE('F261',(#511,#522),#500,.F.);
#524=CARTESIAN_POINT('',(0.,-15.8242,0.));
#525=DIRECTION('',(0.,-1.,0.));
#526=DIRECTION('',(0.,0.,-1.));
#527=AXIS2_PLACEMENT_3D('',#524,#525,#526);
#528=CYLINDRICAL_SURFACE('',#527,22.5806);
#529=ORIENTED_EDGE('',*,*,#491,.T.);
#530=EDGE_LOOP('',(#529));
#531=FACE_BOUND('',#530,.T.);
#532=ORIENTED_EDGE('',*,*,#519,.F.);
#533=EDGE_LOOP('',(#532));
#534=FACE_BOUND('',#533,.T.);
#535=ADVANCED_FACE('F263',(#531,#534),#528,.T.);
#536=CARTESIAN_POINT('',(0.,25.4,0.));
#537=DIRECTION('',(0.,-1.,0.));
#538=DIRECTION('',(0.,0.,-1.));
#539=AXIS2_PLACEMENT_3D('',#536,#537,#538);
#540=PLANE('',#539);
#541=DIRECTION('',(0.,0.,1.));
#542=VECTOR('',#541,1.);
#543=CARTESIAN_POINT('',(9.11949320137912,25.4,-28.575));
#544=LINE('',#543,#542);
#545=CARTESIAN_POINT('',(9.11949320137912,25.4,-16.7253503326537));
#546=VERTEX_POINT('',#545);
#547=CARTESIAN_POINT('',(9.11949320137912,25.4,0.));
#548=VERTEX_POINT('',#547);
#549=EDGE_CURVE('E251',#546,#548,#544,.T.);
#550=ORIENTED_EDGE('',*,*,#549,.F.);
#551=CARTESIAN_POINT('',(0.,25.4,0.));
#552=DIRECTION('',(0.,-1.,0.));
#553=DIRECTION('',(0.,0.,-1.));
#554=AXIS2_PLACEMENT_3D('',#551,#552,#553);
#555=CIRCLE('',#554,19.05);
#556=CARTESIAN_POINT('',(-9.11949320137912,25.4,-16.7253503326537));
#557=VERTEX_POINT('',#556);
#558=EDGE_CURVE('E128',#546,#557,#555,.T.);
#559=ORIENTED_EDGE('',*,*,#558,.T.);
#560=DIRECTION('',(0.,0.,1.));
#561=VECTOR('',#560,1.);
#562=CARTESIAN_POINT('',(-9.11949320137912,25.4,-28.575));
#563=LINE('',#562,#561);
#564=CARTESIAN_POINT('',(-9.11949320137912,25.4,0.));
#565=VERTEX_POINT('',#564);
#566=EDGE_CURVE('E205',#565,#557,#563,.F.);
#567=ORIENTED_EDGE('',*,*,#566,.F.);
#568=DIRECTION('',(-1.,0.,0.));
#569=VECTOR('',#568,1.);
#570=CARTESIAN_POINT('',(0.,25.4,0.));
#571=LINE('',#570,#569);
#572=EDGE_CURVE('E177',#548,#565,#571,.T.);
#573=ORIENTED_EDGE('',*,*,#572,.F.);
#574=EDGE_LOOP('',(#550,#559,#567,#573));
#575=FACE_BOUND('',#574,.T.);
#576=ADVANCED_FACE('F215',(#575),#540,.T.);
#577=CARTESIAN_POINT('',(0.,25.4,0.));
#578=DIRECTION('',(0.,-1.,0.));
#579=DIRECTION('',(0.,0.,-1.));
#580=AXIS2_PLACEMENT_3D('',#577,#578,#579);
#581=CYLINDRICAL_SURFACE('',#580,19.05);
#582=ORIENTED_EDGE('',*,*,#558,.F.);
#583=CARTESIAN_POINT('',(9.11949320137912,25.4,-16.7253503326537));
#584=CARTESIAN_POINT('',(9.19992753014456,25.2844821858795,-16.6814937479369));
#585=CARTESIAN_POINT('',(9.27823444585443,25.1673444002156,-16.6380438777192));
#586=CARTESIAN_POINT('',(9.4304800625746,24.9299313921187,-16.5522258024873));
#587=CARTESIAN_POINT('',(9.50442004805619,24.8096571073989,-16.5098572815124));
#588=CARTESIAN_POINT('',(9.7196988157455,24.4439929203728,-16.3846734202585));
#589=CARTESIAN_POINT('',(9.85437311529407,24.1939385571,-16.303847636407));
#590=CARTESIAN_POINT('',(10.1058215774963,23.6805822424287,-16.1492050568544));
#591=CARTESIAN_POINT('',(10.2224646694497,23.4172002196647,-16.075440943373));
#592=CARTESIAN_POINT('',(10.4356538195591,22.8799191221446,-15.9378709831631));
#593=CARTESIAN_POINT('',(10.5322032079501,22.6060217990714,-15.8740634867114));
#594=CARTESIAN_POINT('',(10.7046067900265,22.0474909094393,-15.7583234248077));
#595=CARTESIAN_POINT('',(10.7803372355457,21.7628041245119,-15.7064621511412));
#596=CARTESIAN_POINT('',(10.9092624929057,21.1861017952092,-15.6171912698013));
#597=CARTESIAN_POINT('',(10.9624564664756,20.8940859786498,-15.5797821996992));
#598=CARTESIAN_POINT('',(11.0452364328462,20.3062494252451,-15.5212057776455));
#599=CARTESIAN_POINT('',(11.0749122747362,20.0104475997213,-15.4999766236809));
#600=CARTESIAN_POINT('',(11.1104274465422,19.4167021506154,-15.474540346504));
#601=CARTESIAN_POINT('',(11.1162699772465,19.1187588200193,-15.4703309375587));
#602=CARTESIAN_POINT('',(11.1047113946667,18.5572911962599,-15.4786269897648));
#603=CARTESIAN_POINT('',(11.0898620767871,18.2936817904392,-15.4892975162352));
#604=CARTESIAN_POINT('',(11.0415681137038,17.7690595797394,-15.5237609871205));
#605=CARTESIAN_POINT('',(11.0081247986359,17.508046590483,-15.5475529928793));
#606=CARTESIAN_POINT('',(10.9230688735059,16.9900970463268,-15.6074264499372));
#607=CARTESIAN_POINT('',(10.8714326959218,16.7331662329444,-15.6435238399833));
#608=CARTESIAN_POINT('',(10.7506661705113,16.2252906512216,-15.7267621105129));
#609=CARTESIAN_POINT('',(10.6815350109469,15.974346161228,-15.7739035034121));
#610=CARTESIAN_POINT('',(10.5265714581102,15.4798397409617,-15.8777350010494));
#611=CARTESIAN_POINT('',(10.4407469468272,15.2362743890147,-15.9344205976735));
#612=CARTESIAN_POINT('',(10.2531644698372,14.7573913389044,-16.0557658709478));
#613=CARTESIAN_POINT('',(10.1514009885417,14.522076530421,-16.1204283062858));
#614=CARTESIAN_POINT('',(9.82333410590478,13.8298239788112,-16.3239292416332));
#615=CARTESIAN_POINT('',(9.57414150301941,13.3862224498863,-16.4723601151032));
#616=CARTESIAN_POINT('',(9.13457366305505,12.7147140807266,-16.7181633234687));
#617=CARTESIAN_POINT('',(8.9621647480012,12.473137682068,-16.8114250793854));
#618=CARTESIAN_POINT('',(8.59904822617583,12.005026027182,-17.0000197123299));
#619=CARTESIAN_POINT('',(8.4083457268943,11.7784866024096,-17.0953520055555));
#620=CARTESIAN_POINT('',(8.00920155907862,11.3410338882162,-17.2859531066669));
#621=CARTESIAN_POINT('',(7.80073773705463,11.1301407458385,-17.3812216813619));
#622=CARTESIAN_POINT('',(7.36712980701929,10.7252780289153,-17.5693976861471));
#623=CARTESIAN_POINT('',(7.14199152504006,10.53130259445,-17.662305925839));
#624=CARTESIAN_POINT('',(6.65150815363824,10.1419665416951,-17.853184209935));
#625=CARTESIAN_POINT('',(6.38441705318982,9.94856225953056,-17.9506749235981));
#626=CARTESIAN_POINT('',(5.83207627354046,9.5851264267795,-18.1376513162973));
#627=CARTESIAN_POINT('',(5.54682499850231,9.41509693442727,-18.2271362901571));
#628=CARTESIAN_POINT('',(4.95996517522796,9.10026660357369,-18.3954982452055));
#629=CARTESIAN_POINT('',(4.65836756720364,8.95544915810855,-18.4743822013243));
#630=CARTESIAN_POINT('',(4.04069049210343,8.69272906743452,-18.6192343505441));
#631=CARTESIAN_POINT('',(3.72461315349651,8.574822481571,-18.6852044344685));
#632=CARTESIAN_POINT('',(3.10795230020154,8.37647773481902,-18.7971490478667));
#633=CARTESIAN_POINT('',(2.8083420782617,8.29370362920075,-18.8443480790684));
#634=CARTESIAN_POINT('',(2.20144320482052,8.15329019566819,-18.9248463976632));
#635=CARTESIAN_POINT('',(1.89415493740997,8.09564961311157,-18.9581463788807));
#636=CARTESIAN_POINT('',(1.27481127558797,8.00643507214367,-19.0098355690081));
#637=CARTESIAN_POINT('',(0.962759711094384,7.97484119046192,-19.0282361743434));
#638=CARTESIAN_POINT('',(0.336587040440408,7.93817336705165,-19.0496011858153));
#639=CARTESIAN_POINT('',(0.022466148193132,7.93309672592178,-19.0525671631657));
#640=CARTESIAN_POINT('',(-0.566931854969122,7.94854136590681,-19.0435609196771));
#641=CARTESIAN_POINT('',(-0.842321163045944,7.96604694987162,-19.0333485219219));
#642=CARTESIAN_POINT('',(-1.39033396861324,8.02138024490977,-19.0011785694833));
#643=CARTESIAN_POINT('',(-1.66295773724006,8.05920594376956,-18.9792221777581));
#644=CARTESIAN_POINT('',(-2.20354362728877,8.15470732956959,-18.9240780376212));
#645=CARTESIAN_POINT('',(-2.47150564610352,8.21238345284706,-18.8908900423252));
#646=CARTESIAN_POINT('',(-3.00103198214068,8.34691189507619,-18.8140344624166));
#647=CARTESIAN_POINT('',(-3.26259605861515,8.42376493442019,-18.7703664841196));
#648=CARTESIAN_POINT('',(-3.778067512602,8.595920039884,-18.6734455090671));
#649=CARTESIAN_POINT('',(-4.03196612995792,8.69124235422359,-18.6201819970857));
#650=CARTESIAN_POINT('',(-4.53058281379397,8.89940903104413,-18.5051833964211));
#651=CARTESIAN_POINT('',(-4.77529757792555,9.01225962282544,-18.4434452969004));
#652=CARTESIAN_POINT('',(-5.25431318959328,9.25449725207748,-18.3127366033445));
#653=CARTESIAN_POINT('',(-5.4886159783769,9.38388118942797,-18.2437673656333));
#654=CARTESIAN_POINT('',(-5.94603090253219,9.65832576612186,-18.0998545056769));
#655=CARTESIAN_POINT('',(-6.16913897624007,9.80339203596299,-18.0249087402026));
#656=CARTESIAN_POINT('',(-6.62783871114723,10.1255077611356,-17.8616909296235));
#657=CARTESIAN_POINT('',(-6.86199889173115,10.3043191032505,-17.7728693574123));
#658=CARTESIAN_POINT('',(-7.31455843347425,10.679143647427,-17.5914519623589));
#659=CARTESIAN_POINT('',(-7.53295668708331,10.8751580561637,-17.4988558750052));
#660=CARTESIAN_POINT('',(-7.95345535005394,11.2836479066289,-17.3117896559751));
#661=CARTESIAN_POINT('',(-8.15553626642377,11.4961424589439,-17.2173174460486));
#662=CARTESIAN_POINT('',(-8.54235623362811,11.9365124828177,-17.0287098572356));
#663=CARTESIAN_POINT('',(-8.72709473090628,12.1643884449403,-16.9345744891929));
#664=CARTESIAN_POINT('',(-9.09787008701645,12.6607365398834,-16.7385766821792));
#665=CARTESIAN_POINT('',(-9.28179221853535,12.9309115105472,-16.6370106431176));
#666=CARTESIAN_POINT('',(-9.62605399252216,13.4881648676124,-16.440222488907));
#667=CARTESIAN_POINT('',(-9.78639007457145,13.7752457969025,-16.3450013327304));
#668=CARTESIAN_POINT('',(-10.081825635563,14.3646021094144,-16.1644435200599));
#669=CARTESIAN_POINT('',(-10.216958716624,14.6668565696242,-16.0790937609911));
#670=CARTESIAN_POINT('',(-10.4606070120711,15.2852050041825,-15.9216605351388));
#671=CARTESIAN_POINT('',(-10.569131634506,15.6012940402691,-15.8495723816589));
#672=CARTESIAN_POINT('',(-10.7359942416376,16.1703354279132,-15.7368537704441));
#673=CARTESIAN_POINT('',(-10.8001342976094,16.4209226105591,-15.6928051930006));
#674=CARTESIAN_POINT('',(-10.9110146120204,16.92758940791,-15.6159158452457));
#675=CARTESIAN_POINT('',(-10.9577585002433,17.1836678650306,-15.5830727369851));
#676=CARTESIAN_POINT('',(-11.0332068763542,17.6994910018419,-15.5297452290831));
#677=CARTESIAN_POINT('',(-11.0619292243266,17.9592317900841,-15.5092485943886));
#678=CARTESIAN_POINT('',(-11.1009936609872,18.4808061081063,-15.481312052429));
#679=CARTESIAN_POINT('',(-11.1113353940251,18.7426396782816,-15.4738723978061));
#680=CARTESIAN_POINT('',(-11.1134798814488,19.2667453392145,-15.4723323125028));
#681=CARTESIAN_POINT('',(-11.105259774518,19.5290175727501,-15.4782483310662));
#682=CARTESIAN_POINT('',(-11.0703601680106,20.0516934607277,-15.503228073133));
#683=CARTESIAN_POINT('',(-11.0436805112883,20.3120970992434,-15.5222919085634));
#684=CARTESIAN_POINT('',(-10.9722175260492,20.8294253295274,-15.5728883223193));
#685=CARTESIAN_POINT('',(-10.9274166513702,21.086346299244,-15.6044329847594));
#686=CARTESIAN_POINT('',(-10.8203100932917,21.5948114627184,-15.6788913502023));
#687=CARTESIAN_POINT('',(-10.758004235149,21.8463556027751,-15.7218051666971));
#688=CARTESIAN_POINT('',(-10.616792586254,22.3420502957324,-15.8175046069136));
#689=CARTESIAN_POINT('',(-10.5379319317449,22.5862189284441,-15.8702633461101));
#690=CARTESIAN_POINT('',(-10.3642708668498,23.0668296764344,-15.9842170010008));
#691=CARTESIAN_POINT('',(-10.2694640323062,23.3032686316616,-16.0454153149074));
#692=CARTESIAN_POINT('',(-9.96250484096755,23.9990006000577,-16.2391299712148));
#693=CARTESIAN_POINT('',(-9.72753998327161,24.4456573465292,-16.3819596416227));
#694=CARTESIAN_POINT('',(-9.35470185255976,25.0518157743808,-16.5954322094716));
#695=CARTESIAN_POINT('',(-9.23941567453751,25.2277988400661,-16.6599711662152));
#696=CARTESIAN_POINT('',(-9.11949320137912,25.4,-16.7253503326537));
#697=B_SPLINE_CURVE_WITH_KNOTS('',3,(#583,#584,#585,#586,#587,#588,#589,#590,#591,#592,#593,
#594,#595,#596,#597,#598,#599,#600,#601,#602,#603,#604,#605,#606,#607,#608,#609,#610,#611,#612,
#613,#614,#615,#616,#617,#618,#619,#620,#621,#622,#623,#624,#625,#626,#627,#628,#629,#630,#631,
#632,#633,#634,#635,#636,#637,#638,#639,#640,#641,#642,#643,#644,#645,#646,#647,#648,#649,#650,
#651,#652,#653,#654,#655,#656,#657,#658,#659,#660,#661,#662,#663,#664,#665,#666,#667,#668,#669,
#670,#671,#672,#673,#674,#675,#676,#677,#678,#679,#680,#681,#682,#683,#684,#685,#686,#687,#688,
#689,#690,#691,#692,#693,#694,#695,#696),.UNSPECIFIED.,.F.,.F.,(4,2,2,2,2,2,2,2,2,2,2,2,2,2,2,2,
2,2,2,2,2,2,2,2,2,2,2,2,2,2,2,2,2,2,2,2,2,2,2,2,2,2,2,2,2,2,2,2,2,2,2,2,2,2,2,2,4),(0.,
0.442257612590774,0.884384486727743,1.76931460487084,2.66040213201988,3.55134185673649,
4.44746814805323,5.34362776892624,6.23634695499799,7.12894624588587,7.92068723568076,
8.71237159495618,9.50508531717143,10.2978358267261,11.0902129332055,11.8828648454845,
13.4670349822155,14.3996081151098,15.3319216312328,16.2654155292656,17.1985847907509,
18.2288600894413,19.2592260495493,20.2889107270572,21.3184445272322,22.2602902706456,
23.202088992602,24.1431666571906,25.0841485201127,25.9115543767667,26.7388783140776,
27.5662204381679,28.3935936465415,29.2218791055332,30.0504596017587,30.8788849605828,
31.70760874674,32.6298309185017,33.5521178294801,34.4754907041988,35.3988930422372,
36.4243895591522,37.4500407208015,38.4743144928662,39.4982255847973,40.2845929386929,
41.0707961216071,41.856218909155,42.6416568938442,43.4280627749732,44.2144753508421,
45.0016512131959,45.7888349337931,46.5738996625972,47.3592814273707,48.9270543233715,
49.5867887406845),.UNSPECIFIED.);
#698=EDGE_CURVE('E195',#546,#557,#697,.T.);
#699=ORIENTED_EDGE('',*,*,#698,.T.);
#700=EDGE_LOOP('',(#582,#699));
#701=FACE_BOUND('',#700,.T.);
#702=CARTESIAN_POINT('',(0.,-25.4,0.));
#703=DIRECTION('',(0.,-1.,0.));
#704=DIRECTION('',(0.,0.,-1.));
#705=AXIS2_PLACEMENT_3D('',#702,#703,#704);
#706=CIRCLE('',#705,19.05);
#707=CARTESIAN_POINT('',(0.,-25.4,-19.05));
#708=VERTEX_POINT('',#707);
#709=EDGE_CURVE('E134',#708,#708,#706,.T.);
#710=ORIENTED_EDGE('',*,*,#709,.T.);
#711=EDGE_LOOP('',(#710));
#712=FACE_BOUND('',#711,.T.);
#713=ADVANCED_FACE('F209',(#701,#712),#581,.F.);
#714=CARTESIAN_POINT('',(0.,-25.4,0.));
#715=DIRECTION('',(0.,1.,0.));
#716=DIRECTION('',(0.,0.,1.));
#717=AXIS2_PLACEMENT_3D('',#714,#715,#716);
#718=PLANE('',#717);
#719=CARTESIAN_POINT('',(0.,-25.4,0.));
#720=DIRECTION('',(0.,1.,0.));
#721=DIRECTION('',(0.,0.,1.));
#722=AXIS2_PLACEMENT_3D('',#719,#720,#721);
#723=CIRCLE('',#722,25.019);
#724=CARTESIAN_POINT('',(0.,-25.4,25.019));
#725=VERTEX_POINT('',#724);
#726=EDGE_CURVE('E164',#725,#725,#723,.F.);
#727=ORIENTED_EDGE('',*,*,#726,.T.);
#728=EDGE_LOOP('',(#727));
#729=FACE_BOUND('',#728,.T.);
#730=ORIENTED_EDGE('',*,*,#709,.F.);
#731=EDGE_LOOP('',(#730));
#732=FACE_BOUND('',#731,.T.);
#733=ADVANCED_FACE('F214',(#729,#732),#718,.F.);
#734=CARTESIAN_POINT('',(0.,-23.2392416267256,0.));
#735=DIRECTION('',(0.,1.,0.));
#736=DIRECTION('',(0.,0.,1.));
#737=AXIS2_PLACEMENT_3D('',#734,#735,#736);
#738=CIRCLE('',#737,25.4);
#739=CARTESIAN_POINT('',(0.,-23.2392416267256,25.4));
#740=VERTEX_POINT('',#739);
#741=EDGE_CURVE('E141',#740,#740,#738,.T.);
#742=ORIENTED_EDGE('',*,*,#741,.T.);
#743=EDGE_LOOP('',(#742));
#744=FACE_BOUND('',#743,.T.);
#745=ORIENTED_EDGE('',*,*,#508,.F.);
#746=EDGE_LOOP('',(#745));
#747=FACE_BOUND('',#746,.T.);
#748=ADVANCED_FACE('F236',(#744,#747),#452,.T.);
#749=CARTESIAN_POINT('',(0.,-4.699,0.));
#750=DIRECTION('',(0.,-1.,0.));
#751=DIRECTION('',(0.,0.,-1.));
#752=AXIS2_PLACEMENT_3D('',#749,#750,#751);
#753=PLANE('',#752);
#754=CARTESIAN_POINT('',(0.,-4.699,0.));
#755=DIRECTION('',(0.,-1.,0.));
#756=DIRECTION('',(0.,0.,-1.));
#757=AXIS2_PLACEMENT_3D('',#754,#755,#756);
#758=CIRCLE('',#757,25.4);
#759=CARTESIAN_POINT('',(0.,-4.699,-25.4));
#760=VERTEX_POINT('',#759);
#761=EDGE_CURVE('E155',#760,#760,#758,.F.);
#762=ORIENTED_EDGE('',*,*,#761,.F.);
#763=EDGE_LOOP('',(#762));
#764=FACE_BOUND('',#763,.T.);
#765=CARTESIAN_POINT('',(0.,-4.699,0.));
#766=DIRECTION('',(0.,-1.,0.));
#767=DIRECTION('',(0.,0.,-1.));
#768=AXIS2_PLACEMENT_3D('',#765,#766,#767);
#769=CIRCLE('',#768,22.5806);
#770=CARTESIAN_POINT('',(0.,-4.699,-22.5806));
#771=VERTEX_POINT('',#770);
#772=EDGE_CURVE('E156',#771,#771,#769,.T.);
#773=ORIENTED_EDGE('',*,*,#772,.F.);
#774=EDGE_LOOP('',(#773));
#775=FACE_BOUND('',#774,.T.);
#776=ADVANCED_FACE('F239',(#764,#775),#753,.T.);
#777=CARTESIAN_POINT('',(0.,-9.525,0.));
#778=DIRECTION('',(0.,-1.,0.));
#779=DIRECTION('',(0.,0.,-1.));
#780=AXIS2_PLACEMENT_3D('',#777,#778,#779);
#781=PLANE('',#780);
#782=ORIENTED_EDGE('',*,*,#460,.T.);
#783=EDGE_LOOP('',(#782));
#784=FACE_BOUND('',#783,.T.);
#785=CARTESIAN_POINT('',(0.,-9.525,0.));
#786=DIRECTION('',(0.,-1.,0.));
#787=DIRECTION('',(0.,0.,-1.));
#788=AXIS2_PLACEMENT_3D('',#785,#786,#787);
#789=CIRCLE('',#788,22.5806);
#790=CARTESIAN_POINT('',(0.,-9.525,-22.5806));
#791=VERTEX_POINT('',#790);
#792=EDGE_CURVE('E247',#791,#791,#789,.T.);
#793=ORIENTED_EDGE('',*,*,#792,.T.);
#794=EDGE_LOOP('',(#793));
#795=FACE_BOUND('',#794,.T.);
#796=ADVANCED_FACE('F242',(#784,#795),#781,.F.);
#797=CARTESIAN_POINT('',(0.,-4.699,0.));
#798=DIRECTION('',(0.,-1.,0.));
#799=DIRECTION('',(0.,0.,-1.));
#800=AXIS2_PLACEMENT_3D('',#797,#798,#799);
#801=CYLINDRICAL_SURFACE('',#800,22.5806);
#802=ORIENTED_EDGE('',*,*,#772,.T.);
#803=EDGE_LOOP('',(#802));
#804=FACE_BOUND('',#803,.T.);
#805=ORIENTED_EDGE('',*,*,#792,.F.);
#806=EDGE_LOOP('',(#805));
#807=FACE_BOUND('',#806,.T.);
#808=ADVANCED_FACE('F190',(#804,#807),#801,.T.);
#809=CARTESIAN_POINT('',(0.,33.3248,0.));
#810=DIRECTION('',(0.,1.,0.));
#811=DIRECTION('',(0.,0.,1.));
#812=AXIS2_PLACEMENT_3D('',#809,#810,#811);
#813=PLANE('',#812);
#814=CARTESIAN_POINT('',(-15.8172376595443,33.3248,-17.201116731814));
#815=DIRECTION('',(0.,1.,0.));
#816=DIRECTION('',(0.,0.,1.));
#817=AXIS2_PLACEMENT_3D('',#814,#815,#816);
#818=CIRCLE('',#817,1.1811);
#819=CARTESIAN_POINT('',(-15.8172376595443,33.3248,-16.020016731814));
#820=VERTEX_POINT('',#819);
#821=EDGE_CURVE('E457',#820,#820,#818,.T.);
#822=ORIENTED_EDGE('',*,*,#821,.F.);
#823=EDGE_LOOP('',(#822));
#824=FACE_BOUND('',#823,.T.);
#825=CARTESIAN_POINT('',(15.8172376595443,33.3248,17.201116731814));
#826=DIRECTION('',(0.,1.,0.));
#827=DIRECTION('',(0.,0.,1.));
#828=AXIS2_PLACEMENT_3D('',#825,#826,#827);
#829=CIRCLE('',#828,1.18110000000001);
#830=CARTESIAN_POINT('',(15.8172376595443,33.3248,18.382216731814));
#831=VERTEX_POINT('',#830);
#832=EDGE_CURVE('E449',#831,#831,#829,.T.);
#833=ORIENTED_EDGE('',*,*,#832,.F.);
#834=EDGE_LOOP('',(#833));
#835=FACE_BOUND('',#834,.T.);
#836=ORIENTED_EDGE('',*,*,#79,.T.);
#837=EDGE_LOOP('',(#836));
#838=FACE_BOUND('',#837,.T.);
#839=ADVANCED_FACE('F218',(#824,#835,#838),#813,.T.);
#840=ORIENTED_EDGE('',*,*,#173,.T.);
#841=DIRECTION('',(0.,-1.,0.));
#842=VECTOR('',#841,1.);
#843=CARTESIAN_POINT('',(-22.5665644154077,199.899972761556,-17.5294265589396));
#844=LINE('',#843,#842);
#845=EDGE_CURVE('E12',#168,#42,#844,.T.);
#846=ORIENTED_EDGE('',*,*,#845,.T.);
#847=ORIENTED_EDGE('',*,*,#62,.T.);
#848=DIRECTION('',(0.,-1.,0.));
#849=VECTOR('',#848,1.);
#850=CARTESIAN_POINT('',(15.5796269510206,211.806222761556,23.9542449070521));
#851=LINE('',#850,#849);
#852=EDGE_CURVE('E409',#172,#59,#851,.T.);
#853=ORIENTED_EDGE('',*,*,#852,.F.);
#854=EDGE_LOOP('',(#840,#846,#847,#853));
#855=FACE_BOUND('',#854,.T.);
#856=ADVANCED_FACE('F118',(#855),#272,.T.);
#857=ORIENTED_EDGE('',*,*,#31,.F.);
#858=EDGE_LOOP('',(#857));
#859=FACE_BOUND('',#858,.T.);
#860=ORIENTED_EDGE('',*,*,#761,.T.);
#861=EDGE_LOOP('',(#860));
#862=FACE_BOUND('',#861,.T.);
#863=ADVANCED_FACE('F231',(#859,#862),#452,.T.);
#864=CARTESIAN_POINT('',(0.,-23.2392416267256,0.));
#865=DIRECTION('',(0.,1.,0.));
#866=DIRECTION('',(0.,0.,1.));
#867=AXIS2_PLACEMENT_3D('',#864,#865,#866);
#868=CONICAL_SURFACE('',#867,25.4,0.17453292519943);
#869=ORIENTED_EDGE('',*,*,#726,.F.);
#870=EDGE_LOOP('',(#869));
#871=FACE_BOUND('',#870,.T.);
#872=ORIENTED_EDGE('',*,*,#741,.F.);
#873=EDGE_LOOP('',(#872));
#874=FACE_BOUND('',#873,.T.);
#875=ADVANCED_FACE('F188',(#871,#874),#868,.T.);
#876=CARTESIAN_POINT('',(0.,19.05,-28.575));
#877=DIRECTION('',(0.,0.,1.));
#878=DIRECTION('',(1.,0.,0.));
#879=AXIS2_PLACEMENT_3D('',#876,#877,#878);
#880=CYLINDRICAL_SURFACE('',#879,11.1125);
#881=ORIENTED_EDGE('',*,*,#549,.T.);
#882=CARTESIAN_POINT('',(0.,19.05,0.));
#883=DIRECTION('',(0.,0.,1.));
#884=DIRECTION('',(1.,0.,0.));
#885=AXIS2_PLACEMENT_3D('',#882,#883,#884);
#886=CIRCLE('',#885,11.1125);
#887=EDGE_CURVE('E206',#548,#565,#886,.T.);
#888=ORIENTED_EDGE('',*,*,#887,.T.);
#889=ORIENTED_EDGE('',*,*,#566,.T.);
#890=ORIENTED_EDGE('',*,*,#698,.F.);
#891=EDGE_LOOP('',(#881,#888,#889,#890));
#892=FACE_BOUND('',#891,.T.);
#893=ORIENTED_EDGE('',*,*,#435,.F.);
#894=ORIENTED_EDGE('',*,*,#263,.T.);
#895=EDGE_LOOP('',(#893,#894));
#896=FACE_BOUND('',#895,.T.);
#897=ADVANCED_FACE('F182',(#892,#896),#880,.F.);
#898=CARTESIAN_POINT('',(0.,19.05,0.));
#899=DIRECTION('',(0.,0.,1.));
#900=DIRECTION('',(1.,0.,0.));
#901=AXIS2_PLACEMENT_3D('',#898,#899,#900);
#902=PLANE('',#901);
#903=ORIENTED_EDGE('',*,*,#572,.T.);
#904=ORIENTED_EDGE('',*,*,#887,.F.);
#905=EDGE_LOOP('',(#903,#904));
#906=FACE_BOUND('',#905,.T.);
#907=ADVANCED_FACE('F187',(#906),#902,.F.);
#908=CARTESIAN_POINT('',(22.5665644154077,211.806222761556,17.5294265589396));
#909=DIRECTION('',(0.676875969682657,0.,0.736097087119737));
#910=DIRECTION('',(0.736097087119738,0.,-0.676875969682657));
#911=AXIS2_PLACEMENT_3D('',#908,#909,#910);
#912=PLANE('',#911);
#913=ORIENTED_EDGE('',*,*,#852,.T.);
#914=ORIENTED_EDGE('',*,*,#60,.T.);
#915=ORIENTED_EDGE('',*,*,#442,.F.);
#916=ORIENTED_EDGE('',*,*,#250,.F.);
#917=EDGE_LOOP('',(#913,#914,#915,#916));
#918=FACE_BOUND('',#917,.T.);
#919=ADVANCED_FACE('F325',(#918),#912,.T.);
#920=CARTESIAN_POINT('',(-22.5665644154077,199.899972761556,-17.5294265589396));
#921=DIRECTION('',(-0.676875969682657,0.,-0.736097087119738));
#922=DIRECTION('',(-0.736097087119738,0.,0.676875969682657));
#923=AXIS2_PLACEMENT_3D('',#920,#921,#922);
#924=PLANE('',#923);
#925=ORIENTED_EDGE('',*,*,#277,.T.);
#926=ORIENTED_EDGE('',*,*,#43,.T.);
#927=ORIENTED_EDGE('',*,*,#845,.F.);
#928=ORIENTED_EDGE('',*,*,#169,.F.);
#929=EDGE_LOOP('',(#925,#926,#927,#928));
#930=FACE_BOUND('',#929,.T.);
#931=ADVANCED_FACE('F107',(#930),#924,.T.);
#932=CARTESIAN_POINT('',(15.8172376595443,23.7998,17.201116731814));
#933=DIRECTION('',(0.,1.,0.));
#934=DIRECTION('',(0.,0.,1.));
#935=AXIS2_PLACEMENT_3D('',#932,#933,#934);
#936=CYLINDRICAL_SURFACE('',#935,1.18110000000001);
#937=CARTESIAN_POINT('',(15.8172376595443,23.7998,17.201116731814));
#938=DIRECTION('',(0.,1.,0.));
#939=DIRECTION('',(0.,0.,1.));
#940=AXIS2_PLACEMENT_3D('',#937,#938,#939);
#941=CIRCLE('',#940,1.18110000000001);
#942=CARTESIAN_POINT('',(15.8172376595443,23.7998,18.382216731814));
#943=VERTEX_POINT('',#942);
#944=EDGE_CURVE('E453',#943,#943,#941,.T.);
#945=CARTESIAN_POINT('',(15.8172376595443,23.7998,18.382216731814));
#946=CARTESIAN_POINT('',(15.8172376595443,23.89901875,18.382216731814));
#947=CARTESIAN_POINT('',(15.8172376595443,23.9982375,18.382216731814));
#948=CARTESIAN_POINT('',(15.8172376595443,24.196675,18.382216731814));
#949=CARTESIAN_POINT('',(15.8172376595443,24.29589375,18.382216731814));
#950=CARTESIAN_POINT('',(15.8172376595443,24.49433125,18.382216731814));
#951=CARTESIAN_POINT('',(15.8172376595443,24.59355,18.382216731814));
#952=CARTESIAN_POINT('',(15.8172376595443,24.7919875,18.382216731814));
#953=CARTESIAN_POINT('',(15.8172376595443,24.89120625,18.382216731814));
#954=CARTESIAN_POINT('',(15.8172376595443,25.08964375,18.382216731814));
#955=CARTESIAN_POINT('',(15.8172376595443,25.1888625,18.382216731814));
#956=CARTESIAN_POINT('',(15.8172376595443,25.3873,18.382216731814));
#957=CARTESIAN_POINT('',(15.8172376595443,25.48651875,18.382216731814));
#958=CARTESIAN_POINT('',(15.8172376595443,25.68495625,18.382216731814));
#959=CARTESIAN_POINT('',(15.8172376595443,25.784175,18.382216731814));
#960=CARTESIAN_POINT('',(15.8172376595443,25.9826125,18.382216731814));
#961=CARTESIAN_POINT('',(15.8172376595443,26.08183125,18.382216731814));
#962=CARTESIAN_POINT('',(15.8172376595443,26.28026875,18.382216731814));
#963=CARTESIAN_POINT('',(15.8172376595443,26.3794875,18.382216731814));
#964=CARTESIAN_POINT('',(15.8172376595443,26.577925,18.382216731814));
#965=CARTESIAN_POINT('',(15.8172376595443,26.67714375,18.382216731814));
#966=CARTESIAN_POINT('',(15.8172376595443,26.87558125,18.382216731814));
#967=CARTESIAN_POINT('',(15.8172376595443,26.9748,18.382216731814));
#968=CARTESIAN_POINT('',(15.8172376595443,27.1732375,18.382216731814));
#969=CARTESIAN_POINT('',(15.8172376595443,27.27245625,18.382216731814));
#970=CARTESIAN_POINT('',(15.8172376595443,27.47089375,18.382216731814));
#971=CARTESIAN_POINT('',(15.8172376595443,27.5701125,18.382216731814));
#972=CARTESIAN_POINT('',(15.8172376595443,27.76855,18.382216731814));
#973=CARTESIAN_POINT('',(15.8172376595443,27.86776875,18.382216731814));
#974=CARTESIAN_POINT('',(15.8172376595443,28.06620625,18.382216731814));
#975=CARTESIAN_POINT('',(15.8172376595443,28.165425,18.382216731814));
#976=CARTESIAN_POINT('',(15.8172376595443,28.3638625,18.382216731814));
#977=CARTESIAN_POINT('',(15.8172376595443,28.46308125,18.382216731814));
#978=CARTESIAN_POINT('',(15.8172376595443,28.66151875,18.382216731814));
#979=CARTESIAN_POINT('',(15.8172376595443,28.7607375,18.382216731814));
#980=CARTESIAN_POINT('',(15.8172376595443,28.959175,18.382216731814));
#981=CARTESIAN_POINT('',(15.8172376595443,29.05839375,18.382216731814));
#982=CARTESIAN_POINT('',(15.8172376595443,29.25683125,18.382216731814));
#983=CARTESIAN_POINT('',(15.8172376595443,29.35605,18.382216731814));
#984=CARTESIAN_POINT('',(15.8172376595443,29.5544875,18.382216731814));
#985=CARTESIAN_POINT('',(15.8172376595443,29.65370625,18.382216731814));
#986=CARTESIAN_POINT('',(15.8172376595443,29.85214375,18.382216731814));
#987=CARTESIAN_POINT('',(15.8172376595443,29.9513625,18.382216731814));
#988=CARTESIAN_POINT('',(15.8172376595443,30.1498,18.382216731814));
#989=CARTESIAN_POINT('',(15.8172376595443,30.24901875,18.382216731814));
#990=CARTESIAN_POINT('',(15.8172376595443,30.44745625,18.382216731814));
#991=CARTESIAN_POINT('',(15.8172376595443,30.546675,18.382216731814));
#992=CARTESIAN_POINT('',(15.8172376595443,30.7451125,18.382216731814));
#993=CARTESIAN_POINT('',(15.8172376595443,30.84433125,18.382216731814));
#994=CARTESIAN_POINT('',(15.8172376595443,31.04276875,18.382216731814));
#995=CARTESIAN_POINT('',(15.8172376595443,31.1419875,18.382216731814));
#996=CARTESIAN_POINT('',(15.8172376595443,31.340425,18.382216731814));
#997=CARTESIAN_POINT('',(15.8172376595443,31.43964375,18.382216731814));
#998=CARTESIAN_POINT('',(15.8172376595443,31.63808125,18.382216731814));
#999=CARTESIAN_POINT('',(15.8172376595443,31.7373,18.382216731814));
#1000=CARTESIAN_POINT('',(15.8172376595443,31.9357375,18.382216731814));
#1001=CARTESIAN_POINT('',(15.8172376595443,32.03495625,18.382216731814));
#1002=CARTESIAN_POINT('',(15.8172376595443,32.23339375,18.382216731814));
#1003=CARTESIAN_POINT('',(15.8172376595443,32.3326125,18.382216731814));
#1004=CARTESIAN_POINT('',(15.8172376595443,32.53105,18.382216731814));
#1005=CARTESIAN_POINT('',(15.8172376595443,32.63026875,18.382216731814));
#1006=CARTESIAN_POINT('',(15.8172376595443,32.82870625,18.382216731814));
#1007=CARTESIAN_POINT('',(15.8172376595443,32.927925,18.382216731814));
#1008=CARTESIAN_POINT('',(15.8172376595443,33.1263625,18.382216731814));
#1009=CARTESIAN_POINT('',(15.8172376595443,33.22558125,18.382216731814));
#1010=CARTESIAN_POINT('',(15.8172376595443,33.3248,18.382216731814));
#1011=B_SPLINE_CURVE_WITH_KNOTS('',3,(#945,#946,#947,#948,#949,#950,#951,#952,#953,#954,#955,
#956,#957,#958,#959,#960,#961,#962,#963,#964,#965,#966,#967,#968,#969,#970,#971,#972,#973,#974,
#975,#976,#977,#978,#979,#980,#981,#982,#983,#984,#985,#986,#987,#988,#989,#990,#991,#992,#993,
#994,#995,#996,#997,#998,#999,#1000,#1001,#1002,#1003,#1004,#1005,#1006,#1007,#1008,#1009,
#1010),.UNSPECIFIED.,.F.,.F.,(4,2,2,2,2,2,2,2,2,2,2,2,2,2,2,2,2,2,2,2,2,2,2,2,2,2,2,2,2,2,2,2,
4),(0.,0.29765625,0.5953125,0.892968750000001,1.190625,1.48828125,1.7859375,2.08359375,2.38125,
2.67890625,2.9765625,3.27421875,3.571875,3.86953125,4.1671875,4.46484375,4.7625,5.06015625,
5.3578125,5.65546875,5.953125,6.25078125,6.5484375,6.84609375,7.14375,7.44140625,7.7390625,
8.03671875,8.334375,8.63203125,8.92968749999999,9.22734375,9.525),.UNSPECIFIED.);
#1012=EDGE_CURVE('BSEAM353',#943,#831,#1011,.T.);
#1013=ORIENTED_EDGE('',*,*,#944,.F.);
#1014=ORIENTED_EDGE('',*,*,#832,.T.);
#1015=ORIENTED_EDGE('',*,*,#1012,.T.);
#1016=ORIENTED_EDGE('',*,*,#1012,.F.);
#1017=EDGE_LOOP('',(#1013,#1015,#1014,#1016));
#1018=FACE_BOUND('',#1017,.T.);
#1019=ADVANCED_FACE('F353',(#1018),#936,.F.);
#1020=CARTESIAN_POINT('',(15.8172376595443,23.7998,17.201116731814));
#1021=DIRECTION('',(0.,1.,0.));
#1022=DIRECTION('',(0.,0.,1.));
#1023=AXIS2_PLACEMENT_3D('',#1020,#1021,#1022);
#1024=PLANE('',#1023);
#1025=ORIENTED_EDGE('',*,*,#944,.T.);
#1026=EDGE_LOOP('',(#1025));
#1027=FACE_BOUND('',#1026,.T.);
#1028=ADVANCED_FACE('F360',(#1027),#1024,.T.);
#1029=CARTESIAN_POINT('',(-15.8172376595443,23.7998,-17.201116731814));
#1030=DIRECTION('',(0.,1.,0.));
#1031=DIRECTION('',(0.,0.,1.));
#1032=AXIS2_PLACEMENT_3D('',#1029,#1030,#1031);
#1033=CYLINDRICAL_SURFACE('',#1032,1.1811);
#1034=CARTESIAN_POINT('',(-15.8172376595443,23.7998,-17.201116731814));
#1035=DIRECTION('',(0.,1.,0.));
#1036=DIRECTION('',(0.,0.,1.));
#1037=AXIS2_PLACEMENT_3D('',#1034,#1035,#1036);
#1038=CIRCLE('',#1037,1.1811);
#1039=CARTESIAN_POINT('',(-15.8172376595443,23.7998,-16.020016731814));
#1040=VERTEX_POINT('',#1039);
#1041=EDGE_CURVE('E406',#1040,#1040,#1038,.T.);
#1042=CARTESIAN_POINT('',(-15.8172376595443,23.7998,-16.020016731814));
#1043=CARTESIAN_POINT('',(-15.8172376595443,23.89901875,-16.020016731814));
#1044=CARTESIAN_POINT('',(-15.8172376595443,23.9982375,-16.020016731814));
#1045=CARTESIAN_POINT('',(-15.8172376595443,24.196675,-16.020016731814));
#1046=CARTESIAN_POINT('',(-15.8172376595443,24.29589375,-16.020016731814));
#1047=CARTESIAN_POINT('',(-15.8172376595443,24.49433125,-16.020016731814));
#1048=CARTESIAN_POINT('',(-15.8172376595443,24.59355,-16.020016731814));
#1049=CARTESIAN_POINT('',(-15.8172376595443,24.7919875,-16.020016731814));
#1050=CARTESIAN_POINT('',(-15.8172376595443,24.89120625,-16.020016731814));
#1051=CARTESIAN_POINT('',(-15.8172376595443,25.08964375,-16.020016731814));
#1052=CARTESIAN_POINT('',(-15.8172376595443,25.1888625,-16.020016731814));
#1053=CARTESIAN_POINT('',(-15.8172376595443,25.3873,-16.020016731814));
#1054=CARTESIAN_POINT('',(-15.8172376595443,25.48651875,-16.020016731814));
#1055=CARTESIAN_POINT('',(-15.8172376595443,25.68495625,-16.020016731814));
#1056=CARTESIAN_POINT('',(-15.8172376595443,25.784175,-16.020016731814));
#1057=CARTESIAN_POINT('',(-15.8172376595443,25.9826125,-16.020016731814));
#1058=CARTESIAN_POINT('',(-15.8172376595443,26.08183125,-16.020016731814));
#1059=CARTESIAN_POINT('',(-15.8172376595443,26.28026875,-16.020016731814));
#1060=CARTESIAN_POINT('',(-15.8172376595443,26.3794875,-16.020016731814));
#1061=CARTESIAN_POINT('',(-15.8172376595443,26.577925,-16.020016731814));
#1062=CARTESIAN_POINT('',(-15.8172376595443,26.67714375,-16.020016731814));
#1063=CARTESIAN_POINT('',(-15.8172376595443,26.87558125,-16.020016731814));
#1064=CARTESIAN_POINT('',(-15.8172376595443,26.9748,-16.020016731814));
#1065=CARTESIAN_POINT('',(-15.8172376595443,27.1732375,-16.020016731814));
#1066=CARTESIAN_POINT('',(-15.8172376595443,27.27245625,-16.020016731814));
#1067=CARTESIAN_POINT('',(-15.8172376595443,27.47089375,-16.020016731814));
#1068=CARTESIAN_POINT('',(-15.8172376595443,27.5701125,-16.020016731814));
#1069=CARTESIAN_POINT('',(-15.8172376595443,27.76855,-16.020016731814));
#1070=CARTESIAN_POINT('',(-15.8172376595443,27.86776875,-16.020016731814));
#1071=CARTESIAN_POINT('',(-15.8172376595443,28.06620625,-16.020016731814));
#1072=CARTESIAN_POINT('',(-15.8172376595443,28.165425,-16.020016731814));
#1073=CARTESIAN_POINT('',(-15.8172376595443,28.3638625,-16.020016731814));
#1074=CARTESIAN_POINT('',(-15.8172376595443,28.46308125,-16.020016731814));
#1075=CARTESIAN_POINT('',(-15.8172376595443,28.66151875,-16.020016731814));
#1076=CARTESIAN_POINT('',(-15.8172376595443,28.7607375,-16.020016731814));
#1077=CARTESIAN_POINT('',(-15.8172376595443,28.959175,-16.020016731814));
#1078=CARTESIAN_POINT('',(-15.8172376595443,29.05839375,-16.020016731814));
#1079=CARTESIAN_POINT('',(-15.8172376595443,29.25683125,-16.020016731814));
#1080=CARTESIAN_POINT('',(-15.8172376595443,29.35605,-16.020016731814));
#1081=CARTESIAN_POINT('',(-15.8172376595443,29.5544875,-16.020016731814));
#1082=CARTESIAN_POINT('',(-15.8172376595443,29.65370625,-16.020016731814));
#1083=CARTESIAN_POINT('',(-15.8172376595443,29.85214375,-16.020016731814));
#1084=CARTESIAN_POINT('',(-15.8172376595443,29.9513625,-16.020016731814));
#1085=CARTESIAN_POINT('',(-15.8172376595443,30.1498,-16.020016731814));
#1086=CARTESIAN_POINT('',(-15.8172376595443,30.24901875,-16.020016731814));
#1087=CARTESIAN_POINT('',(-15.8172376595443,30.44745625,-16.020016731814));
#1088=CARTESIAN_POINT('',(-15.8172376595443,30.546675,-16.020016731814));
#1089=CARTESIAN_POINT('',(-15.8172376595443,30.7451125,-16.020016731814));
#1090=CARTESIAN_POINT('',(-15.8172376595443,30.84433125,-16.020016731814));
#1091=CARTESIAN_POINT('',(-15.8172376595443,31.04276875,-16.020016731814));
#1092=CARTESIAN_POINT('',(-15.8172376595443,31.1419875,-16.020016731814));
#1093=CARTESIAN_POINT('',(-15.8172376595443,31.340425,-16.020016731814));
#1094=CARTESIAN_POINT('',(-15.8172376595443,31.43964375,-16.020016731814));
#1095=CARTESIAN_POINT('',(-15.8172376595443,31.63808125,-16.020016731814));
#1096=CARTESIAN_POINT('',(-15.8172376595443,31.7373,-16.020016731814));
#1097=CARTESIAN_POINT('',(-15.8172376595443,31.9357375,-16.020016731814));
#1098=CARTESIAN_POINT('',(-15.8172376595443,32.03495625,-16.020016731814));
#1099=CARTESIAN_POINT('',(-15.8172376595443,32.23339375,-16.020016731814));
#1100=CARTESIAN_POINT('',(-15.8172376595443,32.3326125,-16.020016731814));
#1101=CARTESIAN_POINT('',(-15.8172376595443,32.53105,-16.020016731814));
#1102=CARTESIAN_POINT('',(-15.8172376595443,32.63026875,-16.020016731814));
#1103=CARTESIAN_POINT('',(-15.8172376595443,32.82870625,-16.020016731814));
#1104=CARTESIAN_POINT('',(-15.8172376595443,32.927925,-16.020016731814));
#1105=CARTESIAN_POINT('',(-15.8172376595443,33.1263625,-16.020016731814));
#1106=CARTESIAN_POINT('',(-15.8172376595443,33.22558125,-16.020016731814));
#1107=CARTESIAN_POINT('',(-15.8172376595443,33.3248,-16.020016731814));
#1108=B_SPLINE_CURVE_WITH_KNOTS('',3,(#1042,#1043,#1044,#1045,#1046,#1047,#1048,#1049,#1050,
#1051,#1052,#1053,#1054,#1055,#1056,#1057,#1058,#1059,#1060,#1061,#1062,#1063,#1064,#1065,#1066,
#1067,#1068,#1069,#1070,#1071,#1072,#1073,#1074,#1075,#1076,#1077,#1078,#1079,#1080,#1081,#1082,
#1083,#1084,#1085,#1086,#1087,#1088,#1089,#1090,#1091,#1092,#1093,#1094,#1095,#1096,#1097,#1098,
#1099,#1100,#1101,#1102,#1103,#1104,#1105,#1106,#1107),.UNSPECIFIED.,.F.,.F.,(4,2,2,2,2,2,2,2,2,
2,2,2,2,2,2,2,2,2,2,2,2,2,2,2,2,2,2,2,2,2,2,2,4),(0.,0.29765625,0.5953125,0.892968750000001,
1.190625,1.48828125,1.7859375,2.08359375,2.38125,2.67890625,2.9765625,3.27421875,3.571875,
3.86953125,4.1671875,4.46484375,4.7625,5.06015625,5.3578125,5.65546875,5.953125,6.25078125,
6.5484375,6.84609375,7.14375,7.44140625,7.7390625,8.03671875,8.334375,8.63203125,
8.92968749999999,9.22734375,9.525),.UNSPECIFIED.);
#1109=EDGE_CURVE('BSEAM368',#1040,#820,#1108,.T.);
#1110=ORIENTED_EDGE('',*,*,#1041,.F.);
#1111=ORIENTED_EDGE('',*,*,#821,.T.);
#1112=ORIENTED_EDGE('',*,*,#1109,.T.);
#1113=ORIENTED_EDGE('',*,*,#1109,.F.);
#1114=EDGE_LOOP('',(#1110,#1112,#1111,#1113));
#1115=FACE_BOUND('',#1114,.T.);
#1116=ADVANCED_FACE('F368',(#1115),#1033,.F.);
#1117=CARTESIAN_POINT('',(-15.8172376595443,23.7998,-17.201116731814));
#1118=DIRECTION('',(0.,1.,0.));
#1119=DIRECTION('',(0.,0.,1.));
#1120=AXIS2_PLACEMENT_3D('',#1117,#1118,#1119);
#1121=PLANE('',#1120);
#1122=ORIENTED_EDGE('',*,*,#1041,.T.);
#1123=EDGE_LOOP('',(#1122));
#1124=FACE_BOUND('',#1123,.T.);
#1125=ADVANCED_FACE('F376',(#1124),#1121,.T.);
#1126=CLOSED_SHELL('',(#66,#267,#447,#475,#495,#523,#535,#576,#713,#733,#748,#776,#796,#808,
#839,#856,#863,#875,#897,#907,#919,#931,#1019,#1028,#1116,#1125));
#1127=MANIFOLD_SOLID_BREP('B2',#1126);
#1128=ADVANCED_BREP_SHAPE_REPRESENTATION('',(#18,#1127),#14);
#1129=SHAPE_DEFINITION_REPRESENTATION(#9,#1128);
ENDSEC;
END-ISO-10303-21;
